###############################################################
#  Generated by:      Cadence Innovus 21.10-p004_1
#  OS:                Linux x86_64(Host ID UETLHR)
#  Generated on:      Wed Nov 23 18:34:10 2022
#  Design:            SoC_Tile
#  Command:           write_lef_abstract SoC_Tile.lef -top_layer met4 -stripe_pins -pg_pin_layers met4
###############################################################

VERSION 5.8 ;

BUSBITCHARS "[]" ;
DIVIDERCHAR "/" ;

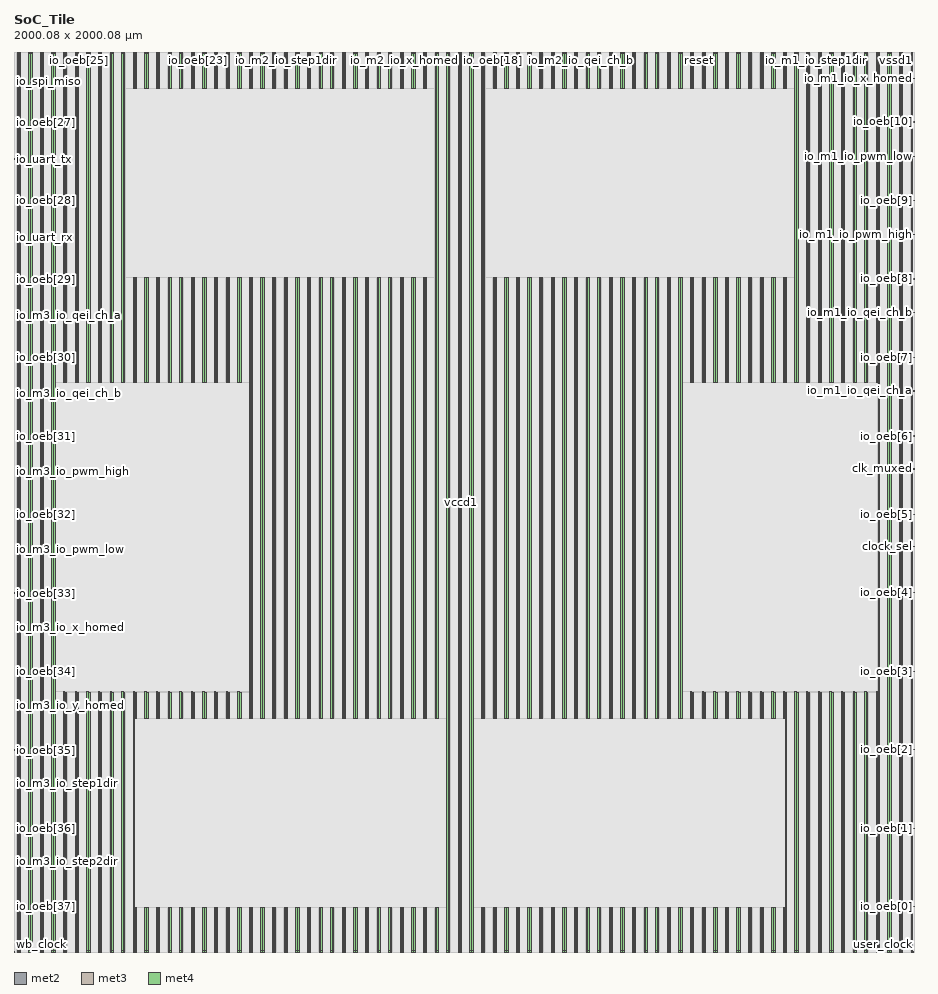
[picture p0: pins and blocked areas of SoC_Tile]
MACRO SoC_Tile
  CLASS BLOCK ;
  SIZE 2000.080000 BY 2000.080000 ;
  FOREIGN SoC_Tile 0.000000 0.000000 ;
  ORIGIN 0 0 ;
  SYMMETRY X Y R90 ;
  PIN user_clock
    DIRECTION INPUT ;
    USE SIGNAL ;
    ANTENNAPARTIALMETALAREA 0.1666 LAYER met2  ;
    ANTENNAPARTIALMETALSIDEAREA 0.672 LAYER met2  ;
    ANTENNAPARTIALCUTAREA 0.04 LAYER via2  ;
    ANTENNAPARTIALMETALAREA 285.163 LAYER met3  ;
    ANTENNAPARTIALMETALSIDEAREA 1521.34 LAYER met3  ;
    ANTENNAPARTIALCUTAREA 0.04 LAYER via3  ;
    ANTENNAPARTIALMETALAREA 0.6516 LAYER met4  ;
    ANTENNAPARTIALMETALSIDEAREA 4.416 LAYER met4  ;
    ANTENNAMODEL OXIDE1 ;
    ANTENNAGATEAREA 0.2475 LAYER met4  ;
    ANTENNAMAXAREACAR 17.5527 LAYER met4  ;
    ANTENNAMAXSIDEAREACAR 98.9939 LAYER met4  ;
    ANTENNAMAXCUTCAR 0.530909 LAYER via4  ;
    PORT
      LAYER met2 ;
        RECT 1999.780000 0.000000 1999.920000 0.485000 ;
    END
  END user_clock
  PIN wb_clock
    DIRECTION INPUT ;
    USE SIGNAL ;
    ANTENNAPARTIALMETALAREA 0.1666 LAYER met2  ;
    ANTENNAPARTIALMETALSIDEAREA 0.672 LAYER met2  ;
    ANTENNAPARTIALCUTAREA 0.04 LAYER via2  ;
    ANTENNAPARTIALMETALAREA 302.344 LAYER met3  ;
    ANTENNAPARTIALMETALSIDEAREA 1612.97 LAYER met3  ;
    ANTENNAPARTIALCUTAREA 0.04 LAYER via3  ;
    ANTENNAPARTIALMETALAREA 0.3258 LAYER met4  ;
    ANTENNAPARTIALMETALSIDEAREA 2.208 LAYER met4  ;
    ANTENNAMODEL OXIDE1 ;
    ANTENNAGATEAREA 0.2475 LAYER met4  ;
    ANTENNAMAXAREACAR 30.9105 LAYER met4  ;
    ANTENNAMAXSIDEAREACAR 167.519 LAYER met4  ;
    ANTENNAMAXCUTCAR 0.530909 LAYER via4  ;
    PORT
      LAYER met2 ;
        RECT 0.160000 0.000000 0.300000 0.485000 ;
    END
  END wb_clock
  PIN clock_sel
    DIRECTION INPUT ;
    USE SIGNAL ;
    ANTENNAPARTIALMETALAREA 20.4744 LAYER met3  ;
    ANTENNAPARTIALMETALSIDEAREA 109.64 LAYER met3  ;
    ANTENNAPARTIALCUTAREA 0.04 LAYER via3  ;
    ANTENNADIFFAREA 0.4347 LAYER met4  ;
    ANTENNAPARTIALMETALAREA 146.368 LAYER met4  ;
    ANTENNAPARTIALMETALSIDEAREA 782.512 LAYER met4  ;
    ANTENNAMODEL OXIDE1 ;
    ANTENNAGATEAREA 0.7425 LAYER met4  ;
    ANTENNAMAXAREACAR 242.909 LAYER met4  ;
    ANTENNAMAXSIDEAREACAR 1291.42 LAYER met4  ;
    ANTENNAMAXCUTCAR 0.530909 LAYER via4  ;
    PORT
      LAYER met3 ;
        RECT 1999.280000 900.110000 2000.080000 900.410000 ;
    END
  END clock_sel
  PIN clk_muxed
    DIRECTION OUTPUT ;
    USE SIGNAL ;
    ANTENNADIFFAREA 4.5209 LAYER met3  ;
    ANTENNAPARTIALMETALAREA 2.5104 LAYER met3  ;
    ANTENNAPARTIALMETALSIDEAREA 13.384 LAYER met3  ;
    PORT
      LAYER met3 ;
        RECT 1999.280000 1073.350000 2000.080000 1073.650000 ;
    END
  END clk_muxed
  PIN reset
    DIRECTION INPUT ;
    USE SIGNAL ;
    ANTENNAPARTIALMETALAREA 17.8079 LAYER met2  ;
    ANTENNAPARTIALMETALSIDEAREA 88.5045 LAYER met2  ;
    ANTENNAMODEL OXIDE1 ;
    ANTENNAGATEAREA 1.7325 LAYER met2  ;
    ANTENNAMAXAREACAR 10.2787 LAYER met2  ;
    ANTENNAMAXSIDEAREACAR 51.0849 LAYER met2  ;
    ANTENNAPARTIALCUTAREA 0.04 LAYER via2  ;
    ANTENNAMAXCUTCAR 0.023088 LAYER via2  ;
    ANTENNAPARTIALMETALAREA 5.506 LAYER met3  ;
    ANTENNAPARTIALMETALSIDEAREA 29.832 LAYER met3  ;
    ANTENNAGATEAREA 1.7325 LAYER met3  ;
    ANTENNAMAXAREACAR 13.4568 LAYER met3  ;
    ANTENNAMAXSIDEAREACAR 68.3039 LAYER met3  ;
    ANTENNAPARTIALCUTAREA 0.04 LAYER via3  ;
    ANTENNAMAXCUTCAR 0.046176 LAYER via3  ;
    ANTENNAPARTIALMETALAREA 117.788 LAYER met4  ;
    ANTENNAPARTIALMETALSIDEAREA 628.672 LAYER met4  ;
    ANTENNAGATEAREA 1.8915 LAYER met4  ;
    ANTENNAMAXAREACAR 75.729 LAYER met4  ;
    ANTENNAMAXSIDEAREACAR 400.671 LAYER met4  ;
    ANTENNAMAXCUTCAR 0.046176 LAYER via4  ;
    PORT
      LAYER met2 ;
        RECT 1521.380000 1999.595000 1521.520000 2000.080000 ;
    END
  END reset
  PIN io_uart_tx
    DIRECTION OUTPUT ;
    USE SIGNAL ;
    ANTENNADIFFAREA 1.782 LAYER met3  ;
    ANTENNAPARTIALMETALAREA 76.071 LAYER met3  ;
    ANTENNAPARTIALMETALSIDEAREA 406.648 LAYER met3  ;
    PORT
      LAYER met3 ;
        RECT 0.000000 1762.040000 0.800000 1762.340000 ;
    END
  END io_uart_tx
  PIN io_uart_rx
    DIRECTION INPUT ;
    USE SIGNAL ;
    ANTENNAPARTIALMETALAREA 20.7766 LAYER met3  ;
    ANTENNAPARTIALMETALSIDEAREA 110.8 LAYER met3  ;
    ANTENNAPARTIALCUTAREA 0.04 LAYER via3  ;
    ANTENNAPARTIALMETALAREA 0.6516 LAYER met4  ;
    ANTENNAPARTIALMETALSIDEAREA 4.416 LAYER met4  ;
    ANTENNAMODEL OXIDE1 ;
    ANTENNAGATEAREA 0.126 LAYER met4  ;
    ANTENNAMAXAREACAR 23.8119 LAYER met4  ;
    ANTENNAMAXSIDEAREACAR 118.73 LAYER met4  ;
    ANTENNAMAXCUTCAR 1.04286 LAYER via4  ;
    PORT
      LAYER met3 ;
        RECT 0.000000 1588.190000 0.800000 1588.490000 ;
    END
  END io_uart_rx
  PIN io_spi_cs
    DIRECTION OUTPUT ;
    USE SIGNAL ;
    ANTENNAPARTIALMETALAREA 74.8488 LAYER met2  ;
    ANTENNAPARTIALMETALSIDEAREA 373.772 LAYER met2  ;
    ANTENNAPARTIALCUTAREA 0.04 LAYER via2  ;
    ANTENNADIFFAREA 1.782 LAYER met3  ;
    ANTENNAPARTIALMETALAREA 45.0138 LAYER met3  ;
    ANTENNAPARTIALMETALSIDEAREA 240.544 LAYER met3  ;
    PORT
      LAYER met2 ;
        RECT 341.940000 1999.595000 342.080000 2000.080000 ;
    END
  END io_spi_cs
  PIN io_spi_clk
    DIRECTION OUTPUT ;
    USE SIGNAL ;
    ANTENNADIFFAREA 1.782 LAYER met2  ;
    ANTENNAPARTIALMETALAREA 62.6847 LAYER met2  ;
    ANTENNAPARTIALMETALSIDEAREA 313.198 LAYER met2  ;
    PORT
      LAYER met2 ;
        RECT 212.680000 1999.595000 212.820000 2000.080000 ;
    END
  END io_spi_clk
  PIN io_spi_mosi
    DIRECTION OUTPUT ;
    USE SIGNAL ;
    ANTENNADIFFAREA 1.782 LAYER met2  ;
    ANTENNAPARTIALMETALAREA 0.6635 LAYER met2  ;
    ANTENNAPARTIALMETALSIDEAREA 3.2095 LAYER met2  ;
    PORT
      LAYER met2 ;
        RECT 82.500000 1999.595000 82.640000 2000.080000 ;
    END
  END io_spi_mosi
  PIN io_spi_miso
    DIRECTION INPUT ;
    USE SIGNAL ;
    ANTENNAPARTIALMETALAREA 20.5936 LAYER met3  ;
    ANTENNAPARTIALMETALSIDEAREA 109.824 LAYER met3  ;
    ANTENNAPARTIALCUTAREA 0.04 LAYER via3  ;
    ANTENNAPARTIALMETALAREA 0.6516 LAYER met4  ;
    ANTENNAPARTIALMETALSIDEAREA 4.416 LAYER met4  ;
    ANTENNAMODEL OXIDE1 ;
    ANTENNAGATEAREA 0.1965 LAYER met4  ;
    ANTENNAMAXAREACAR 45.4382 LAYER met4  ;
    ANTENNAMAXSIDEAREACAR 232.361 LAYER met4  ;
    ANTENNAMAXCUTCAR 0.668702 LAYER via4  ;
    PORT
      LAYER met3 ;
        RECT 0.000000 1935.280000 0.800000 1935.580000 ;
    END
  END io_spi_miso
  PIN io_m1_io_qei_ch_a
    DIRECTION INPUT ;
    USE SIGNAL ;
    ANTENNAPARTIALMETALAREA 3.2004 LAYER met3  ;
    ANTENNAPARTIALMETALSIDEAREA 17.064 LAYER met3  ;
    ANTENNAMODEL OXIDE1 ;
    ANTENNAGATEAREA 0.126 LAYER met3  ;
    ANTENNAMAXAREACAR 30.1706 LAYER met3  ;
    ANTENNAMAXSIDEAREACAR 147.591 LAYER met3  ;
    ANTENNAMAXCUTCAR 0.725397 LAYER via3  ;
    PORT
      LAYER met3 ;
        RECT 1999.280000 1246.590000 2000.080000 1246.890000 ;
    END
  END io_m1_io_qei_ch_a
  PIN io_m1_io_qei_ch_b
    DIRECTION INPUT ;
    USE SIGNAL ;
    ANTENNAPARTIALMETALAREA 0.1644 LAYER met3  ;
    ANTENNAPARTIALMETALSIDEAREA 0.872 LAYER met3  ;
    ANTENNAMODEL OXIDE1 ;
    ANTENNAGATEAREA 0.1965 LAYER met3  ;
    ANTENNAMAXAREACAR 3.38422 LAYER met3  ;
    ANTENNAMAXSIDEAREACAR 13.8601 LAYER met3  ;
    ANTENNAMAXCUTCAR 0.46514 LAYER via3  ;
    PORT
      LAYER met3 ;
        RECT 1999.280000 1420.440000 2000.080000 1420.740000 ;
    END
  END io_m1_io_qei_ch_b
  PIN io_m1_io_pwm_high
    DIRECTION OUTPUT ;
    USE SIGNAL ;
    ANTENNADIFFAREA 1.782 LAYER met3  ;
    ANTENNAPARTIALMETALAREA 4.9944 LAYER met3  ;
    ANTENNAPARTIALMETALSIDEAREA 26.632 LAYER met3  ;
    PORT
      LAYER met3 ;
        RECT 1999.280000 1593.680000 2000.080000 1593.980000 ;
    END
  END io_m1_io_pwm_high
  PIN io_m1_io_pwm_low
    DIRECTION OUTPUT ;
    USE SIGNAL ;
    ANTENNADIFFAREA 1.782 LAYER met3  ;
    ANTENNAPARTIALMETALAREA 5.6844 LAYER met3  ;
    ANTENNAPARTIALMETALSIDEAREA 30.312 LAYER met3  ;
    PORT
      LAYER met3 ;
        RECT 1999.280000 1766.920000 2000.080000 1767.220000 ;
    END
  END io_m1_io_pwm_low
  PIN io_m1_io_x_homed
    DIRECTION INPUT ;
    USE SIGNAL ;
    ANTENNAPARTIALMETALAREA 0.5784 LAYER met3  ;
    ANTENNAPARTIALMETALSIDEAREA 3.08 LAYER met3  ;
    ANTENNAMODEL OXIDE1 ;
    ANTENNAGATEAREA 0.213 LAYER met3  ;
    ANTENNAMAXAREACAR 18.454 LAYER met3  ;
    ANTENNAMAXSIDEAREACAR 90.2911 LAYER met3  ;
    ANTENNAMAXCUTCAR 0.429108 LAYER via3  ;
    PORT
      LAYER met3 ;
        RECT 1999.280000 1940.770000 2000.080000 1941.070000 ;
    END
  END io_m1_io_x_homed
  PIN io_m1_io_y_homed
    DIRECTION INPUT ;
    USE SIGNAL ;
    ANTENNAPARTIALMETALAREA 10.2647 LAYER met2  ;
    ANTENNAPARTIALMETALSIDEAREA 51.2155 LAYER met2  ;
    ANTENNAMODEL OXIDE1 ;
    ANTENNAGATEAREA 0.1965 LAYER met2  ;
    ANTENNAMAXAREACAR 53.2824 LAYER met2  ;
    ANTENNAMAXSIDEAREACAR 263.417 LAYER met2  ;
    ANTENNAMAXCUTCAR 0.261578 LAYER via2  ;
    PORT
      LAYER met2 ;
        RECT 1913.760000 1999.595000 1913.900000 2000.080000 ;
    END
  END io_m1_io_y_homed
  PIN io_m1_io_step1dir
    DIRECTION OUTPUT ;
    USE SIGNAL ;
    ANTENNAPARTIALMETALAREA 86.4766 LAYER met2  ;
    ANTENNAPARTIALMETALSIDEAREA 432.222 LAYER met2  ;
    ANTENNAPARTIALCUTAREA 0.04 LAYER via2  ;
    ANTENNAPARTIALMETALAREA 133.57 LAYER met3  ;
    ANTENNAPARTIALMETALSIDEAREA 712.84 LAYER met3  ;
    ANTENNAPARTIALCUTAREA 0.04 LAYER via3  ;
    ANTENNADIFFAREA 1.782 LAYER met4  ;
    ANTENNAPARTIALMETALAREA 24.2748 LAYER met4  ;
    ANTENNAPARTIALMETALSIDEAREA 129.936 LAYER met4  ;
    PORT
      LAYER met2 ;
        RECT 1782.660000 1999.595000 1782.800000 2000.080000 ;
    END
  END io_m1_io_step1dir
  PIN io_m1_io_step2dir
    DIRECTION OUTPUT ;
    USE SIGNAL ;
    ANTENNAPARTIALMETALAREA 11.1538 LAYER met2  ;
    ANTENNAPARTIALMETALSIDEAREA 55.608 LAYER met2  ;
    ANTENNAPARTIALCUTAREA 0.04 LAYER via2  ;
    ANTENNADIFFAREA 1.782 LAYER met3  ;
    ANTENNAPARTIALMETALAREA 156.496 LAYER met3  ;
    ANTENNAPARTIALMETALSIDEAREA 835.584 LAYER met3  ;
    PORT
      LAYER met2 ;
        RECT 1652.020000 1999.595000 1652.160000 2000.080000 ;
    END
  END io_m1_io_step2dir
  PIN io_m2_io_qei_ch_a
    DIRECTION INPUT ;
    USE SIGNAL ;
    ANTENNAPARTIALMETALAREA 0.6159 LAYER met2  ;
    ANTENNAPARTIALMETALSIDEAREA 2.9715 LAYER met2  ;
    ANTENNAMODEL OXIDE1 ;
    ANTENNAGATEAREA 0.126 LAYER met2  ;
    ANTENNAMAXAREACAR 9.67222 LAYER met2  ;
    ANTENNAMAXSIDEAREACAR 36.6349 LAYER met2  ;
    ANTENNAMAXCUTCAR 0.407937 LAYER via2  ;
    PORT
      LAYER met2 ;
        RECT 1390.280000 1999.595000 1390.420000 2000.080000 ;
    END
  END io_m2_io_qei_ch_a
  PIN io_m2_io_qei_ch_b
    DIRECTION INPUT ;
    USE SIGNAL ;
    ANTENNAPARTIALMETALAREA 0.7447 LAYER met2  ;
    ANTENNAPARTIALMETALSIDEAREA 3.6155 LAYER met2  ;
    ANTENNAMODEL OXIDE1 ;
    ANTENNAGATEAREA 0.126 LAYER met2  ;
    ANTENNAMAXAREACAR 8.97063 LAYER met2  ;
    ANTENNAMAXSIDEAREACAR 33.6627 LAYER met2  ;
    ANTENNAMAXCUTCAR 0.407937 LAYER via2  ;
    PORT
      LAYER met2 ;
        RECT 1259.640000 1999.595000 1259.780000 2000.080000 ;
    END
  END io_m2_io_qei_ch_b
  PIN io_m2_io_pwm_high
    DIRECTION OUTPUT ;
    USE SIGNAL ;
    ANTENNAPARTIALMETALAREA 84.414 LAYER met2  ;
    ANTENNAPARTIALMETALSIDEAREA 421.673 LAYER met2  ;
    ANTENNAPARTIALCUTAREA 0.04 LAYER via2  ;
    ANTENNADIFFAREA 1.782 LAYER met3  ;
    ANTENNAPARTIALMETALAREA 66.1638 LAYER met3  ;
    ANTENNAPARTIALMETALSIDEAREA 353.344 LAYER met3  ;
    PORT
      LAYER met2 ;
        RECT 1129.000000 1999.595000 1129.140000 2000.080000 ;
    END
  END io_m2_io_pwm_high
  PIN io_m2_io_pwm_low
    DIRECTION OUTPUT ;
    USE SIGNAL ;
    ANTENNAPARTIALMETALAREA 60.9854 LAYER met2  ;
    ANTENNAPARTIALMETALSIDEAREA 304.766 LAYER met2  ;
    ANTENNAPARTIALCUTAREA 0.04 LAYER via2  ;
    ANTENNAPARTIALMETALAREA 2.401 LAYER met3  ;
    ANTENNAPARTIALMETALSIDEAREA 13.272 LAYER met3  ;
    ANTENNAPARTIALCUTAREA 0.04 LAYER via3  ;
    ANTENNADIFFAREA 1.782 LAYER met4  ;
    ANTENNAPARTIALMETALAREA 29.5818 LAYER met4  ;
    ANTENNAPARTIALMETALSIDEAREA 158.24 LAYER met4  ;
    PORT
      LAYER met2 ;
        RECT 997.900000 1999.595000 998.040000 2000.080000 ;
    END
  END io_m2_io_pwm_low
  PIN io_m2_io_x_homed
    DIRECTION INPUT ;
    USE SIGNAL ;
    ANTENNAPARTIALMETALAREA 6.5043 LAYER met2  ;
    ANTENNAPARTIALMETALSIDEAREA 32.4135 LAYER met2  ;
    ANTENNAMODEL OXIDE1 ;
    ANTENNAGATEAREA 0.126 LAYER met2  ;
    ANTENNAMAXAREACAR 54.6817 LAYER met2  ;
    ANTENNAMAXSIDEAREACAR 262.218 LAYER met2  ;
    ANTENNAMAXCUTCAR 0.407937 LAYER via2  ;
    PORT
      LAYER met2 ;
        RECT 867.260000 1999.595000 867.400000 2000.080000 ;
    END
  END io_m2_io_x_homed
  PIN io_m2_io_y_homed
    DIRECTION INPUT ;
    USE SIGNAL ;
    ANTENNAPARTIALMETALAREA 3.0771 LAYER met2  ;
    ANTENNAPARTIALMETALSIDEAREA 15.2775 LAYER met2  ;
    ANTENNAMODEL OXIDE1 ;
    ANTENNAGATEAREA 0.213 LAYER met2  ;
    ANTENNAMAXAREACAR 16.0087 LAYER met2  ;
    ANTENNAMAXSIDEAREACAR 77.5258 LAYER met2  ;
    ANTENNAMAXCUTCAR 0.241315 LAYER via2  ;
    PORT
      LAYER met2 ;
        RECT 736.160000 1999.595000 736.300000 2000.080000 ;
    END
  END io_m2_io_y_homed
  PIN io_m2_io_step1dir
    DIRECTION OUTPUT ;
    USE SIGNAL ;
    ANTENNAPARTIALMETALAREA 31.1694 LAYER met2  ;
    ANTENNAPARTIALMETALSIDEAREA 155.568 LAYER met2  ;
    ANTENNAPARTIALCUTAREA 0.04 LAYER via2  ;
    ANTENNAPARTIALMETALAREA 0.2509 LAYER met3  ;
    ANTENNAPARTIALMETALSIDEAREA 1.808 LAYER met3  ;
    ANTENNAPARTIALCUTAREA 0.04 LAYER via3  ;
    ANTENNADIFFAREA 1.782 LAYER met4  ;
    ANTENNAPARTIALMETALAREA 104.66 LAYER met4  ;
    ANTENNAPARTIALMETALSIDEAREA 558.656 LAYER met4  ;
    PORT
      LAYER met2 ;
        RECT 605.520000 1999.595000 605.660000 2000.080000 ;
    END
  END io_m2_io_step1dir
  PIN io_m2_io_step2dir
    DIRECTION OUTPUT ;
    USE SIGNAL ;
    ANTENNAPARTIALMETALAREA 81.2458 LAYER met2  ;
    ANTENNAPARTIALMETALSIDEAREA 405.832 LAYER met2  ;
    ANTENNAPARTIALCUTAREA 0.04 LAYER via2  ;
    ANTENNADIFFAREA 1.782 LAYER met3  ;
    ANTENNAPARTIALMETALAREA 68.6088 LAYER met3  ;
    ANTENNAPARTIALMETALSIDEAREA 366.384 LAYER met3  ;
    PORT
      LAYER met2 ;
        RECT 474.880000 1999.595000 475.020000 2000.080000 ;
    END
  END io_m2_io_step2dir
  PIN io_m3_io_qei_ch_a
    DIRECTION INPUT ;
    USE SIGNAL ;
    ANTENNAPARTIALMETALAREA 20.7766 LAYER met3  ;
    ANTENNAPARTIALMETALSIDEAREA 110.8 LAYER met3  ;
    ANTENNAPARTIALCUTAREA 0.04 LAYER via3  ;
    ANTENNAPARTIALMETALAREA 0.6516 LAYER met4  ;
    ANTENNAPARTIALMETALSIDEAREA 4.416 LAYER met4  ;
    ANTENNAMODEL OXIDE1 ;
    ANTENNAGATEAREA 0.1965 LAYER met4  ;
    ANTENNAMAXAREACAR 62.2417 LAYER met4  ;
    ANTENNAMAXSIDEAREACAR 316.379 LAYER met4  ;
    ANTENNAMAXCUTCAR 0.668702 LAYER via4  ;
    PORT
      LAYER met3 ;
        RECT 0.000000 1414.950000 0.800000 1415.250000 ;
    END
  END io_m3_io_qei_ch_a
  PIN io_m3_io_qei_ch_b
    DIRECTION INPUT ;
    USE SIGNAL ;
    ANTENNAPARTIALMETALAREA 0.4404 LAYER met3  ;
    ANTENNAPARTIALMETALSIDEAREA 2.344 LAYER met3  ;
    ANTENNAMODEL OXIDE1 ;
    ANTENNAGATEAREA 0.1965 LAYER met3  ;
    ANTENNAMAXAREACAR 8.75572 LAYER met3  ;
    ANTENNAMAXSIDEAREACAR 40.7583 LAYER met3  ;
    ANTENNAMAXCUTCAR 0.46514 LAYER via3  ;
    PORT
      LAYER met3 ;
        RECT 0.000000 1241.710000 0.800000 1242.010000 ;
    END
  END io_m3_io_qei_ch_b
  PIN io_m3_io_pwm_high
    DIRECTION OUTPUT ;
    USE SIGNAL ;
    ANTENNADIFFAREA 1.782 LAYER met3  ;
    ANTENNAPARTIALMETALAREA 6.6504 LAYER met3  ;
    ANTENNAPARTIALMETALSIDEAREA 35.464 LAYER met3  ;
    PORT
      LAYER met3 ;
        RECT 0.000000 1067.860000 0.800000 1068.160000 ;
    END
  END io_m3_io_pwm_high
  PIN io_m3_io_pwm_low
    DIRECTION OUTPUT ;
    USE SIGNAL ;
    ANTENNADIFFAREA 1.782 LAYER met3  ;
    ANTENNAPARTIALMETALAREA 6.4644 LAYER met3  ;
    ANTENNAPARTIALMETALSIDEAREA 34.472 LAYER met3  ;
    PORT
      LAYER met3 ;
        RECT 0.000000 894.620000 0.800000 894.920000 ;
    END
  END io_m3_io_pwm_low
  PIN io_m3_io_x_homed
    DIRECTION INPUT ;
    USE SIGNAL ;
    ANTENNAPARTIALMETALAREA 4.6704 LAYER met3  ;
    ANTENNAPARTIALMETALSIDEAREA 24.904 LAYER met3  ;
    ANTENNAMODEL OXIDE1 ;
    ANTENNAGATEAREA 0.126 LAYER met3  ;
    ANTENNAMAXAREACAR 60.4262 LAYER met3  ;
    ANTENNAMAXSIDEAREACAR 299.663 LAYER met3  ;
    ANTENNAMAXCUTCAR 0.725397 LAYER via3  ;
    PORT
      LAYER met3 ;
        RECT 0.000000 721.380000 0.800000 721.680000 ;
    END
  END io_m3_io_x_homed
  PIN io_m3_io_y_homed
    DIRECTION INPUT ;
    USE SIGNAL ;
    ANTENNAPARTIALMETALAREA 1.4064 LAYER met3  ;
    ANTENNAPARTIALMETALSIDEAREA 7.496 LAYER met3  ;
    ANTENNAMODEL OXIDE1 ;
    ANTENNAGATEAREA 0.1965 LAYER met3  ;
    ANTENNAMAXAREACAR 13.0509 LAYER met3  ;
    ANTENNAMAXSIDEAREACAR 64.2163 LAYER met3  ;
    ANTENNAMAXCUTCAR 0.46514 LAYER via3  ;
    PORT
      LAYER met3 ;
        RECT 0.000000 547.530000 0.800000 547.830000 ;
    END
  END io_m3_io_y_homed
  PIN io_m3_io_step1dir
    DIRECTION OUTPUT ;
    USE SIGNAL ;
    ANTENNAPARTIALMETALAREA 8.1544 LAYER met3  ;
    ANTENNAPARTIALMETALSIDEAREA 43.952 LAYER met3  ;
    ANTENNAPARTIALCUTAREA 0.04 LAYER via3  ;
    ANTENNADIFFAREA 1.782 LAYER met4  ;
    ANTENNAPARTIALMETALAREA 64.2408 LAYER met4  ;
    ANTENNAPARTIALMETALSIDEAREA 343.088 LAYER met4  ;
    PORT
      LAYER met3 ;
        RECT 0.000000 374.290000 0.800000 374.590000 ;
    END
  END io_m3_io_step1dir
  PIN io_m3_io_step2dir
    DIRECTION OUTPUT ;
    USE SIGNAL ;
    ANTENNAPARTIALMETALAREA 6.9054 LAYER met3  ;
    ANTENNAPARTIALMETALSIDEAREA 37.272 LAYER met3  ;
    ANTENNAPARTIALCUTAREA 0.04 LAYER via3  ;
    ANTENNADIFFAREA 1.782 LAYER met4  ;
    ANTENNAPARTIALMETALAREA 65.0838 LAYER met4  ;
    ANTENNAPARTIALMETALSIDEAREA 347.584 LAYER met4  ;
    PORT
      LAYER met3 ;
        RECT 0.000000 200.440000 0.800000 200.740000 ;
    END
  END io_m3_io_step2dir
  PIN io_oeb[37]
    DIRECTION OUTPUT ;
    USE SIGNAL ;
    ANTENNADIFFAREA 1.782 LAYER met3  ;
    ANTENNAPARTIALMETALAREA 19.929 LAYER met3  ;
    ANTENNAPARTIALMETALSIDEAREA 108.184 LAYER met3  ;
    PORT
      LAYER met3 ;
        RECT 0.000000 100.400000 0.800000 100.700000 ;
    END
  END io_oeb[37]
  PIN io_oeb[36]
    DIRECTION OUTPUT ;
    USE SIGNAL ;
    ANTENNADIFFAREA 1.782 LAYER met3  ;
    ANTENNAPARTIALMETALAREA 19.809 LAYER met3  ;
    ANTENNAPARTIALMETALSIDEAREA 107.064 LAYER met3  ;
    PORT
      LAYER met3 ;
        RECT 0.000000 274.250000 0.800000 274.550000 ;
    END
  END io_oeb[36]
  PIN io_oeb[35]
    DIRECTION OUTPUT ;
    USE SIGNAL ;
    ANTENNAPARTIALMETALAREA 1.5444 LAYER met3  ;
    ANTENNAPARTIALMETALSIDEAREA 8.232 LAYER met3  ;
    PORT
      LAYER met3 ;
        RECT 0.000000 448.710000 0.800000 449.010000 ;
    END
  END io_oeb[35]
  PIN io_oeb[34]
    DIRECTION OUTPUT ;
    USE SIGNAL ;
    ANTENNAPARTIALMETALAREA 1.5444 LAYER met3  ;
    ANTENNAPARTIALMETALSIDEAREA 8.232 LAYER met3  ;
    PORT
      LAYER met3 ;
        RECT 0.000000 623.170000 0.800000 623.470000 ;
    END
  END io_oeb[34]
  PIN io_oeb[33]
    DIRECTION OUTPUT ;
    USE SIGNAL ;
    ANTENNADIFFAREA 1.782 LAYER met3  ;
    ANTENNAPARTIALMETALAREA 19.929 LAYER met3  ;
    ANTENNAPARTIALMETALSIDEAREA 108.184 LAYER met3  ;
    PORT
      LAYER met3 ;
        RECT 0.000000 797.630000 0.800000 797.930000 ;
    END
  END io_oeb[33]
  PIN io_oeb[32]
    DIRECTION OUTPUT ;
    USE SIGNAL ;
    ANTENNADIFFAREA 1.782 LAYER met3  ;
    ANTENNAPARTIALMETALAREA 1.4163 LAYER met3  ;
    ANTENNAPARTIALMETALSIDEAREA 7.544 LAYER met3  ;
    ANTENNAMODEL OXIDE1 ;
    ANTENNAGATEAREA 0.7425 LAYER met3  ;
    ANTENNAMAXAREACAR 2.56215 LAYER met3  ;
    ANTENNAMAXSIDEAREACAR 11.9576 LAYER met3  ;
    ANTENNAMAXCUTCAR 0.123098 LAYER via3  ;
    PORT
      LAYER met3 ;
        RECT 0.000000 972.090000 0.800000 972.390000 ;
    END
  END io_oeb[32]
  PIN io_oeb[31]
    DIRECTION OUTPUT ;
    USE SIGNAL ;
    ANTENNAPARTIALMETALAREA 1.5444 LAYER met3  ;
    ANTENNAPARTIALMETALSIDEAREA 8.232 LAYER met3  ;
    PORT
      LAYER met3 ;
        RECT 0.000000 1145.940000 0.800000 1146.240000 ;
    END
  END io_oeb[31]
  PIN io_oeb[30]
    DIRECTION OUTPUT ;
    USE SIGNAL ;
    ANTENNAPARTIALMETALAREA 1.5444 LAYER met3  ;
    ANTENNAPARTIALMETALSIDEAREA 8.232 LAYER met3  ;
    PORT
      LAYER met3 ;
        RECT 0.000000 1320.400000 0.800000 1320.700000 ;
    END
  END io_oeb[30]
  PIN io_oeb[29]
    DIRECTION OUTPUT ;
    USE SIGNAL ;
    ANTENNADIFFAREA 1.782 LAYER met3  ;
    ANTENNAPARTIALMETALAREA 1.4163 LAYER met3  ;
    ANTENNAPARTIALMETALSIDEAREA 7.544 LAYER met3  ;
    ANTENNAMODEL OXIDE1 ;
    ANTENNAGATEAREA 0.7425 LAYER met3  ;
    ANTENNAMAXAREACAR 2.51663 LAYER met3  ;
    ANTENNAMAXSIDEAREACAR 11.835 LAYER met3  ;
    ANTENNAMAXCUTCAR 0.123098 LAYER via3  ;
    PORT
      LAYER met3 ;
        RECT 0.000000 1494.860000 0.800000 1495.160000 ;
    END
  END io_oeb[29]
  PIN io_oeb[28]
    DIRECTION OUTPUT ;
    USE SIGNAL ;
    ANTENNAPARTIALMETALAREA 1.5444 LAYER met3  ;
    ANTENNAPARTIALMETALSIDEAREA 8.232 LAYER met3  ;
    PORT
      LAYER met3 ;
        RECT 0.000000 1669.320000 0.800000 1669.620000 ;
    END
  END io_oeb[28]
  PIN io_oeb[27]
    DIRECTION OUTPUT ;
    USE SIGNAL ;
    ANTENNAPARTIALMETALAREA 1.5444 LAYER met3  ;
    ANTENNAPARTIALMETALSIDEAREA 8.232 LAYER met3  ;
    PORT
      LAYER met3 ;
        RECT 0.000000 1843.780000 0.800000 1844.080000 ;
    END
  END io_oeb[27]
  PIN io_oeb[26]
    DIRECTION OUTPUT ;
    USE SIGNAL ;
    ANTENNADIFFAREA 2.673 LAYER met2  ;
    ANTENNAPARTIALMETALAREA 21.0473 LAYER met2  ;
    ANTENNAPARTIALMETALSIDEAREA 105.011 LAYER met2  ;
    ANTENNAMODEL OXIDE1 ;
    ANTENNAGATEAREA 0.7425 LAYER met2  ;
    ANTENNAMAXAREACAR 28.3465 LAYER met2  ;
    ANTENNAMAXSIDEAREACAR 141.428 LAYER met2  ;
    PORT
      LAYER met2 ;
        RECT 13.500000 1999.595000 13.640000 2000.080000 ;
    END
  END io_oeb[26]
  PIN io_oeb[25]
    DIRECTION OUTPUT ;
    USE SIGNAL ;
    ANTENNADIFFAREA 2.673 LAYER met2  ;
    ANTENNAPARTIALMETALAREA 21.0634 LAYER met2  ;
    ANTENNAPARTIALMETALSIDEAREA 105.189 LAYER met2  ;
    ANTENNAMODEL OXIDE1 ;
    ANTENNAGATEAREA 0.7425 LAYER met2  ;
    ANTENNAMAXAREACAR 29.3293 LAYER met2  ;
    ANTENNAMAXSIDEAREACAR 145.238 LAYER met2  ;
    ANTENNAMAXCUTCAR 0.0692256 LAYER via2  ;
    PORT
      LAYER met2 ;
        RECT 145.060000 1999.595000 145.200000 2000.080000 ;
    END
  END io_oeb[25]
  PIN io_oeb[24]
    DIRECTION OUTPUT ;
    USE SIGNAL ;
    ANTENNADIFFAREA 2.673 LAYER met2  ;
    ANTENNAPARTIALMETALAREA 0.4905 LAYER met2  ;
    ANTENNAPARTIALMETALSIDEAREA 2.3345 LAYER met2  ;
    ANTENNAMODEL OXIDE1 ;
    ANTENNAGATEAREA 0.99 LAYER met2  ;
    ANTENNAMAXAREACAR 0.495455 LAYER met2  ;
    ANTENNAMAXSIDEAREACAR 2.35808 LAYER met2  ;
    PORT
      LAYER met2 ;
        RECT 276.620000 1999.595000 276.760000 2000.080000 ;
    END
  END io_oeb[24]
  PIN io_oeb[23]
    DIRECTION OUTPUT ;
    USE SIGNAL ;
    ANTENNADIFFAREA 2.673 LAYER met2  ;
    ANTENNAPARTIALMETALAREA 0.5066 LAYER met2  ;
    ANTENNAPARTIALMETALSIDEAREA 2.513 LAYER met2  ;
    ANTENNAMODEL OXIDE1 ;
    ANTENNAGATEAREA 0.99 LAYER met2  ;
    ANTENNAMAXAREACAR 39.1291 LAYER met2  ;
    ANTENNAMAXSIDEAREACAR 194.178 LAYER met2  ;
    ANTENNAMAXCUTCAR 0.0746465 LAYER via2  ;
    PORT
      LAYER met2 ;
        RECT 408.180000 1999.595000 408.320000 2000.080000 ;
    END
  END io_oeb[23]
  PIN io_oeb[22]
    DIRECTION OUTPUT ;
    USE SIGNAL ;
    ANTENNADIFFAREA 1.782 LAYER met2  ;
    ANTENNAPARTIALMETALAREA 0.2351 LAYER met2  ;
    ANTENNAPARTIALMETALSIDEAREA 1.0675 LAYER met2  ;
    ANTENNAMODEL OXIDE1 ;
    ANTENNAGATEAREA 0.99 LAYER met2  ;
    ANTENNAMAXAREACAR 56.7146 LAYER met2  ;
    ANTENNAMAXSIDEAREACAR 282.194 LAYER met2  ;
    ANTENNAMAXCUTCAR 0.0519192 LAYER via2  ;
    PORT
      LAYER met2 ;
        RECT 539.740000 1999.595000 539.880000 2000.080000 ;
    END
  END io_oeb[22]
  PIN io_oeb[21]
    DIRECTION OUTPUT ;
    USE SIGNAL ;
    ANTENNAPARTIALMETALAREA 0.1399 LAYER met2  ;
    ANTENNAPARTIALMETALSIDEAREA 0.5915 LAYER met2  ;
    PORT
      LAYER met2 ;
        RECT 670.840000 1999.595000 670.980000 2000.080000 ;
    END
  END io_oeb[21]
  PIN io_oeb[20]
    DIRECTION OUTPUT ;
    USE SIGNAL ;
    ANTENNAPARTIALMETALAREA 0.1399 LAYER met2  ;
    ANTENNAPARTIALMETALSIDEAREA 0.5915 LAYER met2  ;
    PORT
      LAYER met2 ;
        RECT 802.400000 1999.595000 802.540000 2000.080000 ;
    END
  END io_oeb[20]
  PIN io_oeb[19]
    DIRECTION OUTPUT ;
    USE SIGNAL ;
    ANTENNADIFFAREA 2.673 LAYER met2  ;
    ANTENNAPARTIALMETALAREA 13.1712 LAYER met2  ;
    ANTENNAPARTIALMETALSIDEAREA 65.492 LAYER met2  ;
    ANTENNAMODEL OXIDE1 ;
    ANTENNAGATEAREA 0.7425 LAYER met2  ;
    ANTENNAMAXAREACAR 18.1473 LAYER met2  ;
    ANTENNAMAXSIDEAREACAR 89.1017 LAYER met2  ;
    ANTENNAMAXCUTCAR 0.0692256 LAYER via2  ;
    PORT
      LAYER met2 ;
        RECT 933.960000 1999.595000 934.100000 2000.080000 ;
    END
  END io_oeb[19]
  PIN io_oeb[18]
    DIRECTION OUTPUT ;
    USE SIGNAL ;
    ANTENNADIFFAREA 2.673 LAYER met2  ;
    ANTENNAPARTIALMETALAREA 13.1712 LAYER met2  ;
    ANTENNAPARTIALMETALSIDEAREA 65.492 LAYER met2  ;
    ANTENNAMODEL OXIDE1 ;
    ANTENNAGATEAREA 0.7425 LAYER met2  ;
    ANTENNAMAXAREACAR 17.739 LAYER met2  ;
    ANTENNAMAXSIDEAREACAR 88.2047 LAYER met2  ;
    PORT
      LAYER met2 ;
        RECT 1064.140000 1999.595000 1064.280000 2000.080000 ;
    END
  END io_oeb[18]
  PIN io_oeb[17]
    DIRECTION OUTPUT ;
    USE SIGNAL ;
    ANTENNAPARTIALMETALAREA 0.2043 LAYER met2  ;
    ANTENNAPARTIALMETALSIDEAREA 0.9135 LAYER met2  ;
    PORT
      LAYER met2 ;
        RECT 1197.080000 1999.595000 1197.220000 2000.080000 ;
    END
  END io_oeb[17]
  PIN io_oeb[16]
    DIRECTION OUTPUT ;
    USE SIGNAL ;
    ANTENNAPARTIALMETALAREA 0.1399 LAYER met2  ;
    ANTENNAPARTIALMETALSIDEAREA 0.5915 LAYER met2  ;
    PORT
      LAYER met2 ;
        RECT 1328.640000 1999.595000 1328.780000 2000.080000 ;
    END
  END io_oeb[16]
  PIN io_oeb[15]
    DIRECTION OUTPUT ;
    USE SIGNAL ;
    ANTENNAPARTIALMETALAREA 0.2106 LAYER met2  ;
    ANTENNAPARTIALMETALSIDEAREA 0.945 LAYER met2  ;
    PORT
      LAYER met2 ;
        RECT 1459.740000 1999.595000 1459.880000 2000.080000 ;
    END
  END io_oeb[15]
  PIN io_oeb[14]
    DIRECTION OUTPUT ;
    USE SIGNAL ;
    ANTENNAPARTIALMETALAREA 17.8079 LAYER met2  ;
    ANTENNAPARTIALMETALSIDEAREA 88.5045 LAYER met2  ;
    ANTENNAMODEL OXIDE1 ;
    ANTENNAGATEAREA 1.7325 LAYER met2  ;
    ANTENNAMAXAREACAR 10.2787 LAYER met2  ;
    ANTENNAMAXSIDEAREACAR 51.0849 LAYER met2  ;
    ANTENNAPARTIALCUTAREA 0.04 LAYER via2  ;
    ANTENNAMAXCUTCAR 0.023088 LAYER via2  ;
    ANTENNAPARTIALMETALAREA 5.506 LAYER met3  ;
    ANTENNAPARTIALMETALSIDEAREA 29.832 LAYER met3  ;
    ANTENNAGATEAREA 1.7325 LAYER met3  ;
    ANTENNAMAXAREACAR 13.4568 LAYER met3  ;
    ANTENNAMAXSIDEAREACAR 68.3039 LAYER met3  ;
    ANTENNAPARTIALCUTAREA 0.04 LAYER via3  ;
    ANTENNAMAXCUTCAR 0.046176 LAYER via3  ;
    ANTENNAPARTIALMETALAREA 117.788 LAYER met4  ;
    ANTENNAPARTIALMETALSIDEAREA 628.672 LAYER met4  ;
    ANTENNAGATEAREA 1.8915 LAYER met4  ;
    ANTENNAMAXAREACAR 75.729 LAYER met4  ;
    ANTENNAMAXSIDEAREACAR 400.671 LAYER met4  ;
    ANTENNAMAXCUTCAR 0.046176 LAYER via4  ;
    PORT
      LAYER met2 ;
        RECT 1591.300000 1999.595000 1591.440000 2000.080000 ;
    END
  END io_oeb[14]
  PIN io_oeb[13]
    DIRECTION OUTPUT ;
    USE SIGNAL ;
    ANTENNAPARTIALMETALAREA 17.8079 LAYER met2  ;
    ANTENNAPARTIALMETALSIDEAREA 88.5045 LAYER met2  ;
    ANTENNAMODEL OXIDE1 ;
    ANTENNAGATEAREA 1.7325 LAYER met2  ;
    ANTENNAMAXAREACAR 13.1997 LAYER met2  ;
    ANTENNAMAXSIDEAREACAR 64.3084 LAYER met2  ;
    ANTENNAPARTIALCUTAREA 0.04 LAYER via2  ;
    ANTENNAMAXCUTCAR 0.122617 LAYER via2  ;
    ANTENNAPARTIALMETALAREA 5.506 LAYER met3  ;
    ANTENNAPARTIALMETALSIDEAREA 29.832 LAYER met3  ;
    ANTENNAGATEAREA 1.7325 LAYER met3  ;
    ANTENNAMAXAREACAR 16.3777 LAYER met3  ;
    ANTENNAMAXSIDEAREACAR 81.5275 LAYER met3  ;
    ANTENNAPARTIALCUTAREA 0.04 LAYER via3  ;
    ANTENNAMAXCUTCAR 0.145705 LAYER via3  ;
    ANTENNAPARTIALMETALAREA 117.788 LAYER met4  ;
    ANTENNAPARTIALMETALSIDEAREA 628.672 LAYER met4  ;
    ANTENNAGATEAREA 1.8915 LAYER met4  ;
    ANTENNAMAXAREACAR 78.6499 LAYER met4  ;
    ANTENNAMAXSIDEAREACAR 413.894 LAYER met4  ;
    ANTENNAMAXCUTCAR 0.826415 LAYER via4  ;
    PORT
      LAYER met2 ;
        RECT 1722.860000 1999.595000 1723.000000 2000.080000 ;
    END
  END io_oeb[13]
  PIN io_oeb[12]
    DIRECTION OUTPUT ;
    USE SIGNAL ;
    ANTENNAPARTIALMETALAREA 0.1399 LAYER met2  ;
    ANTENNAPARTIALMETALSIDEAREA 0.5915 LAYER met2  ;
    PORT
      LAYER met2 ;
        RECT 1854.420000 1999.595000 1854.560000 2000.080000 ;
    END
  END io_oeb[12]
  PIN io_oeb[11]
    DIRECTION OUTPUT ;
    USE SIGNAL ;
    ANTENNAPARTIALMETALAREA 0.1399 LAYER met2  ;
    ANTENNAPARTIALMETALSIDEAREA 0.5915 LAYER met2  ;
    PORT
      LAYER met2 ;
        RECT 1985.980000 1999.595000 1986.120000 2000.080000 ;
    END
  END io_oeb[11]
  PIN io_oeb[10]
    DIRECTION OUTPUT ;
    USE SIGNAL ;
    ANTENNADIFFAREA 1.782 LAYER met3  ;
    ANTENNAPARTIALMETALAREA 11.8572 LAYER met3  ;
    ANTENNAPARTIALMETALSIDEAREA 64.664 LAYER met3  ;
    PORT
      LAYER met3 ;
        RECT 1999.280000 1844.390000 2000.080000 1844.690000 ;
    END
  END io_oeb[10]
  PIN io_oeb[9]
    DIRECTION OUTPUT ;
    USE SIGNAL ;
    ANTENNADIFFAREA 1.782 LAYER met3  ;
    ANTENNAPARTIALMETALAREA 11.7372 LAYER met3  ;
    ANTENNAPARTIALMETALSIDEAREA 63.544 LAYER met3  ;
    PORT
      LAYER met3 ;
        RECT 1999.280000 1669.930000 2000.080000 1670.230000 ;
    END
  END io_oeb[9]
  PIN io_oeb[8]
    DIRECTION OUTPUT ;
    USE SIGNAL ;
    ANTENNAPARTIALMETALAREA 0.8544 LAYER met3  ;
    ANTENNAPARTIALMETALSIDEAREA 4.552 LAYER met3  ;
    PORT
      LAYER met3 ;
        RECT 1999.280000 1495.470000 2000.080000 1495.770000 ;
    END
  END io_oeb[8]
  PIN io_oeb[7]
    DIRECTION OUTPUT ;
    USE SIGNAL ;
    ANTENNAPARTIALMETALAREA 1.1304 LAYER met3  ;
    ANTENNAPARTIALMETALSIDEAREA 6.024 LAYER met3  ;
    PORT
      LAYER met3 ;
        RECT 1999.280000 1321.010000 2000.080000 1321.310000 ;
    END
  END io_oeb[7]
  PIN io_oeb[6]
    DIRECTION OUTPUT ;
    USE SIGNAL ;
    ANTENNADIFFAREA 1.782 LAYER met3  ;
    ANTENNAPARTIALMETALAREA 11.8572 LAYER met3  ;
    ANTENNAPARTIALMETALSIDEAREA 64.664 LAYER met3  ;
    PORT
      LAYER met3 ;
        RECT 1999.280000 1146.550000 2000.080000 1146.850000 ;
    END
  END io_oeb[6]
  PIN io_oeb[5]
    DIRECTION OUTPUT ;
    USE SIGNAL ;
    ANTENNAPARTIALMETALAREA 1.1304 LAYER met3  ;
    ANTENNAPARTIALMETALSIDEAREA 6.024 LAYER met3  ;
    PORT
      LAYER met3 ;
        RECT 1999.280000 972.700000 2000.080000 973.000000 ;
    END
  END io_oeb[5]
  PIN io_oeb[4]
    DIRECTION OUTPUT ;
    USE SIGNAL ;
    ANTENNAPARTIALMETALAREA 0.8544 LAYER met3  ;
    ANTENNAPARTIALMETALSIDEAREA 4.552 LAYER met3  ;
    PORT
      LAYER met3 ;
        RECT 1999.280000 798.240000 2000.080000 798.540000 ;
    END
  END io_oeb[4]
  PIN io_oeb[3]
    DIRECTION OUTPUT ;
    USE SIGNAL ;
    ANTENNAPARTIALMETALAREA 0.5784 LAYER met3  ;
    ANTENNAPARTIALMETALSIDEAREA 3.08 LAYER met3  ;
    PORT
      LAYER met3 ;
        RECT 1999.280000 623.780000 2000.080000 624.080000 ;
    END
  END io_oeb[3]
  PIN io_oeb[2]
    DIRECTION OUTPUT ;
    USE SIGNAL ;
    ANTENNAPARTIALMETALAREA 0.1644 LAYER met3  ;
    ANTENNAPARTIALMETALSIDEAREA 0.872 LAYER met3  ;
    PORT
      LAYER met3 ;
        RECT 1999.280000 449.320000 2000.080000 449.620000 ;
    END
  END io_oeb[2]
  PIN io_oeb[1]
    DIRECTION OUTPUT ;
    USE SIGNAL ;
    ANTENNAPARTIALMETALAREA 0.4404 LAYER met3  ;
    ANTENNAPARTIALMETALSIDEAREA 2.344 LAYER met3  ;
    PORT
      LAYER met3 ;
        RECT 1999.280000 274.860000 2000.080000 275.160000 ;
    END
  END io_oeb[1]
  PIN io_oeb[0]
    DIRECTION OUTPUT ;
    USE SIGNAL ;
    ANTENNAPARTIALMETALAREA 0.4404 LAYER met3  ;
    ANTENNAPARTIALMETALSIDEAREA 2.344 LAYER met3  ;
    PORT
      LAYER met3 ;
        RECT 1999.280000 101.010000 2000.080000 101.310000 ;
    END
  END io_oeb[0]
  PIN vssd1
    DIRECTION INOUT ;
    USE GROUND ;
    PORT
      LAYER met4 ;
        RECT 1142.210000 1996.980000 1145.310000 2000.080000 ;
    END
    PORT
      LAYER met4 ;
        RECT 1142.210000 0.000000 1145.310000 3.100000 ;
    END
    PORT
      LAYER met4 ;
        RECT 1116.410000 1996.980000 1119.510000 2000.080000 ;
    END
    PORT
      LAYER met4 ;
        RECT 1116.410000 0.000000 1119.510000 3.100000 ;
    END
    PORT
      LAYER met4 ;
        RECT 1090.610000 1996.980000 1093.710000 2000.080000 ;
    END
    PORT
      LAYER met4 ;
        RECT 1090.610000 0.000000 1093.710000 3.100000 ;
    END
    PORT
      LAYER met4 ;
        RECT 1064.810000 1996.980000 1067.910000 2000.080000 ;
    END
    PORT
      LAYER met4 ;
        RECT 1064.810000 0.000000 1067.910000 3.100000 ;
    END
    PORT
      LAYER met4 ;
        RECT 1039.010000 1996.980000 1042.110000 2000.080000 ;
    END
    PORT
      LAYER met4 ;
        RECT 1039.010000 0.000000 1042.110000 3.100000 ;
    END
    PORT
      LAYER met4 ;
        RECT 1013.210000 1996.980000 1016.310000 2000.080000 ;
    END
    PORT
      LAYER met4 ;
        RECT 1013.210000 0.000000 1016.310000 3.100000 ;
    END
    PORT
      LAYER met4 ;
        RECT 987.410000 1996.980000 990.510000 2000.080000 ;
    END
    PORT
      LAYER met4 ;
        RECT 987.410000 0.000000 990.510000 3.100000 ;
    END
    PORT
      LAYER met4 ;
        RECT 961.610000 1996.980000 964.710000 2000.080000 ;
    END
    PORT
      LAYER met4 ;
        RECT 961.610000 0.000000 964.710000 3.100000 ;
    END
    PORT
      LAYER met4 ;
        RECT 935.810000 1996.980000 938.910000 2000.080000 ;
    END
    PORT
      LAYER met4 ;
        RECT 935.810000 0.000000 938.910000 3.100000 ;
    END
    PORT
      LAYER met4 ;
        RECT 910.010000 1996.980000 913.110000 2000.080000 ;
    END
    PORT
      LAYER met4 ;
        RECT 910.010000 0.000000 913.110000 3.100000 ;
    END
    PORT
      LAYER met4 ;
        RECT 884.210000 1996.980000 887.310000 2000.080000 ;
    END
    PORT
      LAYER met4 ;
        RECT 884.210000 0.000000 887.310000 3.100000 ;
    END
    PORT
      LAYER met4 ;
        RECT 858.410000 1996.980000 861.510000 2000.080000 ;
    END
    PORT
      LAYER met4 ;
        RECT 858.410000 0.000000 861.510000 3.100000 ;
    END
    PORT
      LAYER met4 ;
        RECT 1993.610000 1996.980000 1996.710000 2000.080000 ;
    END
    PORT
      LAYER met4 ;
        RECT 1993.610000 0.000000 1996.710000 3.100000 ;
    END
    PORT
      LAYER met4 ;
        RECT 832.610000 1996.980000 835.710000 2000.080000 ;
    END
    PORT
      LAYER met4 ;
        RECT 832.610000 0.000000 835.710000 3.100000 ;
    END
    PORT
      LAYER met4 ;
        RECT 1967.810000 1996.980000 1970.910000 2000.080000 ;
    END
    PORT
      LAYER met4 ;
        RECT 1967.810000 0.000000 1970.910000 3.100000 ;
    END
    PORT
      LAYER met4 ;
        RECT 806.810000 1996.980000 809.910000 2000.080000 ;
    END
    PORT
      LAYER met4 ;
        RECT 806.810000 0.000000 809.910000 3.100000 ;
    END
    PORT
      LAYER met4 ;
        RECT 1942.010000 1996.980000 1945.110000 2000.080000 ;
    END
    PORT
      LAYER met4 ;
        RECT 1942.010000 0.000000 1945.110000 3.100000 ;
    END
    PORT
      LAYER met4 ;
        RECT 781.010000 1996.980000 784.110000 2000.080000 ;
    END
    PORT
      LAYER met4 ;
        RECT 781.010000 0.000000 784.110000 3.100000 ;
    END
    PORT
      LAYER met4 ;
        RECT 1916.210000 1996.980000 1919.310000 2000.080000 ;
    END
    PORT
      LAYER met4 ;
        RECT 1916.210000 0.000000 1919.310000 3.100000 ;
    END
    PORT
      LAYER met4 ;
        RECT 755.210000 1996.980000 758.310000 2000.080000 ;
    END
    PORT
      LAYER met4 ;
        RECT 755.210000 0.000000 758.310000 3.100000 ;
    END
    PORT
      LAYER met4 ;
        RECT 1890.410000 1996.980000 1893.510000 2000.080000 ;
    END
    PORT
      LAYER met4 ;
        RECT 1890.410000 0.000000 1893.510000 3.100000 ;
    END
    PORT
      LAYER met4 ;
        RECT 729.410000 1996.980000 732.510000 2000.080000 ;
    END
    PORT
      LAYER met4 ;
        RECT 729.410000 0.000000 732.510000 3.100000 ;
    END
    PORT
      LAYER met4 ;
        RECT 1864.610000 1996.980000 1867.710000 2000.080000 ;
    END
    PORT
      LAYER met4 ;
        RECT 1864.610000 0.000000 1867.710000 3.100000 ;
    END
    PORT
      LAYER met4 ;
        RECT 703.610000 1996.980000 706.710000 2000.080000 ;
    END
    PORT
      LAYER met4 ;
        RECT 703.610000 0.000000 706.710000 3.100000 ;
    END
    PORT
      LAYER met4 ;
        RECT 1838.810000 1996.980000 1841.910000 2000.080000 ;
    END
    PORT
      LAYER met4 ;
        RECT 1838.810000 0.000000 1841.910000 3.100000 ;
    END
    PORT
      LAYER met4 ;
        RECT 677.810000 1996.980000 680.910000 2000.080000 ;
    END
    PORT
      LAYER met4 ;
        RECT 677.810000 0.000000 680.910000 3.100000 ;
    END
    PORT
      LAYER met4 ;
        RECT 1813.010000 1996.980000 1816.110000 2000.080000 ;
    END
    PORT
      LAYER met4 ;
        RECT 1813.010000 0.000000 1816.110000 3.100000 ;
    END
    PORT
      LAYER met4 ;
        RECT 652.010000 1996.980000 655.110000 2000.080000 ;
    END
    PORT
      LAYER met4 ;
        RECT 652.010000 0.000000 655.110000 3.100000 ;
    END
    PORT
      LAYER met4 ;
        RECT 1787.210000 1996.980000 1790.310000 2000.080000 ;
    END
    PORT
      LAYER met4 ;
        RECT 1787.210000 0.000000 1790.310000 3.100000 ;
    END
    PORT
      LAYER met4 ;
        RECT 626.210000 1996.980000 629.310000 2000.080000 ;
    END
    PORT
      LAYER met4 ;
        RECT 626.210000 0.000000 629.310000 3.100000 ;
    END
    PORT
      LAYER met4 ;
        RECT 1761.410000 1996.980000 1764.510000 2000.080000 ;
    END
    PORT
      LAYER met4 ;
        RECT 1761.410000 0.000000 1764.510000 3.100000 ;
    END
    PORT
      LAYER met4 ;
        RECT 600.410000 1996.980000 603.510000 2000.080000 ;
    END
    PORT
      LAYER met4 ;
        RECT 600.410000 0.000000 603.510000 3.100000 ;
    END
    PORT
      LAYER met4 ;
        RECT 1735.610000 1996.980000 1738.710000 2000.080000 ;
    END
    PORT
      LAYER met4 ;
        RECT 1735.610000 0.000000 1738.710000 3.100000 ;
    END
    PORT
      LAYER met4 ;
        RECT 574.610000 1996.980000 577.710000 2000.080000 ;
    END
    PORT
      LAYER met4 ;
        RECT 574.610000 0.000000 577.710000 3.100000 ;
    END
    PORT
      LAYER met4 ;
        RECT 1709.810000 1996.980000 1712.910000 2000.080000 ;
    END
    PORT
      LAYER met4 ;
        RECT 1709.810000 0.000000 1712.910000 3.100000 ;
    END
    PORT
      LAYER met4 ;
        RECT 548.810000 1996.980000 551.910000 2000.080000 ;
    END
    PORT
      LAYER met4 ;
        RECT 548.810000 0.000000 551.910000 3.100000 ;
    END
    PORT
      LAYER met4 ;
        RECT 1684.010000 1996.980000 1687.110000 2000.080000 ;
    END
    PORT
      LAYER met4 ;
        RECT 1684.010000 0.000000 1687.110000 3.100000 ;
    END
    PORT
      LAYER met4 ;
        RECT 523.010000 1996.980000 526.110000 2000.080000 ;
    END
    PORT
      LAYER met4 ;
        RECT 523.010000 0.000000 526.110000 3.100000 ;
    END
    PORT
      LAYER met4 ;
        RECT 1658.210000 1996.980000 1661.310000 2000.080000 ;
    END
    PORT
      LAYER met4 ;
        RECT 1658.210000 0.000000 1661.310000 3.100000 ;
    END
    PORT
      LAYER met4 ;
        RECT 497.210000 1996.980000 500.310000 2000.080000 ;
    END
    PORT
      LAYER met4 ;
        RECT 497.210000 0.000000 500.310000 3.100000 ;
    END
    PORT
      LAYER met4 ;
        RECT 1632.410000 1996.980000 1635.510000 2000.080000 ;
    END
    PORT
      LAYER met4 ;
        RECT 1632.410000 0.000000 1635.510000 3.100000 ;
    END
    PORT
      LAYER met4 ;
        RECT 471.410000 1996.980000 474.510000 2000.080000 ;
    END
    PORT
      LAYER met4 ;
        RECT 471.410000 0.000000 474.510000 3.100000 ;
    END
    PORT
      LAYER met4 ;
        RECT 1606.610000 1996.980000 1609.710000 2000.080000 ;
    END
    PORT
      LAYER met4 ;
        RECT 1606.610000 0.000000 1609.710000 3.100000 ;
    END
    PORT
      LAYER met4 ;
        RECT 445.610000 1996.980000 448.710000 2000.080000 ;
    END
    PORT
      LAYER met4 ;
        RECT 445.610000 0.000000 448.710000 3.100000 ;
    END
    PORT
      LAYER met4 ;
        RECT 1580.810000 1996.980000 1583.910000 2000.080000 ;
    END
    PORT
      LAYER met4 ;
        RECT 1580.810000 0.000000 1583.910000 3.100000 ;
    END
    PORT
      LAYER met4 ;
        RECT 419.810000 1996.980000 422.910000 2000.080000 ;
    END
    PORT
      LAYER met4 ;
        RECT 419.810000 0.000000 422.910000 3.100000 ;
    END
    PORT
      LAYER met4 ;
        RECT 1555.010000 1996.980000 1558.110000 2000.080000 ;
    END
    PORT
      LAYER met4 ;
        RECT 1555.010000 0.000000 1558.110000 3.100000 ;
    END
    PORT
      LAYER met4 ;
        RECT 394.010000 1996.980000 397.110000 2000.080000 ;
    END
    PORT
      LAYER met4 ;
        RECT 394.010000 0.000000 397.110000 3.100000 ;
    END
    PORT
      LAYER met4 ;
        RECT 1529.210000 1996.980000 1532.310000 2000.080000 ;
    END
    PORT
      LAYER met4 ;
        RECT 1529.210000 0.000000 1532.310000 3.100000 ;
    END
    PORT
      LAYER met4 ;
        RECT 368.210000 1996.980000 371.310000 2000.080000 ;
    END
    PORT
      LAYER met4 ;
        RECT 368.210000 0.000000 371.310000 3.100000 ;
    END
    PORT
      LAYER met4 ;
        RECT 1503.410000 1996.980000 1506.510000 2000.080000 ;
    END
    PORT
      LAYER met4 ;
        RECT 1503.410000 0.000000 1506.510000 3.100000 ;
    END
    PORT
      LAYER met4 ;
        RECT 342.410000 1996.980000 345.510000 2000.080000 ;
    END
    PORT
      LAYER met4 ;
        RECT 342.410000 0.000000 345.510000 3.100000 ;
    END
    PORT
      LAYER met4 ;
        RECT 1477.610000 1996.980000 1480.710000 2000.080000 ;
    END
    PORT
      LAYER met4 ;
        RECT 1477.610000 0.000000 1480.710000 3.100000 ;
    END
    PORT
      LAYER met4 ;
        RECT 316.610000 1996.980000 319.710000 2000.080000 ;
    END
    PORT
      LAYER met4 ;
        RECT 316.610000 0.000000 319.710000 3.100000 ;
    END
    PORT
      LAYER met4 ;
        RECT 1451.810000 1996.980000 1454.910000 2000.080000 ;
    END
    PORT
      LAYER met4 ;
        RECT 1451.810000 0.000000 1454.910000 3.100000 ;
    END
    PORT
      LAYER met4 ;
        RECT 290.810000 1996.980000 293.910000 2000.080000 ;
    END
    PORT
      LAYER met4 ;
        RECT 290.810000 0.000000 293.910000 3.100000 ;
    END
    PORT
      LAYER met4 ;
        RECT 1426.010000 1996.980000 1429.110000 2000.080000 ;
    END
    PORT
      LAYER met4 ;
        RECT 1426.010000 0.000000 1429.110000 3.100000 ;
    END
    PORT
      LAYER met4 ;
        RECT 265.010000 1996.980000 268.110000 2000.080000 ;
    END
    PORT
      LAYER met4 ;
        RECT 265.010000 0.000000 268.110000 3.100000 ;
    END
    PORT
      LAYER met4 ;
        RECT 1400.210000 1996.980000 1403.310000 2000.080000 ;
    END
    PORT
      LAYER met4 ;
        RECT 1400.210000 0.000000 1403.310000 3.100000 ;
    END
    PORT
      LAYER met4 ;
        RECT 239.210000 1996.980000 242.310000 2000.080000 ;
    END
    PORT
      LAYER met4 ;
        RECT 239.210000 0.000000 242.310000 3.100000 ;
    END
    PORT
      LAYER met4 ;
        RECT 1374.410000 1996.980000 1377.510000 2000.080000 ;
    END
    PORT
      LAYER met4 ;
        RECT 1374.410000 0.000000 1377.510000 3.100000 ;
    END
    PORT
      LAYER met4 ;
        RECT 213.410000 1996.980000 216.510000 2000.080000 ;
    END
    PORT
      LAYER met4 ;
        RECT 213.410000 0.000000 216.510000 3.100000 ;
    END
    PORT
      LAYER met4 ;
        RECT 1348.610000 1996.980000 1351.710000 2000.080000 ;
    END
    PORT
      LAYER met4 ;
        RECT 1348.610000 0.000000 1351.710000 3.100000 ;
    END
    PORT
      LAYER met4 ;
        RECT 187.610000 1996.980000 190.710000 2000.080000 ;
    END
    PORT
      LAYER met4 ;
        RECT 187.610000 0.000000 190.710000 3.100000 ;
    END
    PORT
      LAYER met4 ;
        RECT 1322.810000 1996.980000 1325.910000 2000.080000 ;
    END
    PORT
      LAYER met4 ;
        RECT 1322.810000 0.000000 1325.910000 3.100000 ;
    END
    PORT
      LAYER met4 ;
        RECT 161.810000 1996.980000 164.910000 2000.080000 ;
    END
    PORT
      LAYER met4 ;
        RECT 161.810000 0.000000 164.910000 3.100000 ;
    END
    PORT
      LAYER met4 ;
        RECT 1297.010000 1996.980000 1300.110000 2000.080000 ;
    END
    PORT
      LAYER met4 ;
        RECT 1297.010000 0.000000 1300.110000 3.100000 ;
    END
    PORT
      LAYER met4 ;
        RECT 136.010000 1996.980000 139.110000 2000.080000 ;
    END
    PORT
      LAYER met4 ;
        RECT 136.010000 0.000000 139.110000 3.100000 ;
    END
    PORT
      LAYER met4 ;
        RECT 1271.210000 1996.980000 1274.310000 2000.080000 ;
    END
    PORT
      LAYER met4 ;
        RECT 1271.210000 0.000000 1274.310000 3.100000 ;
    END
    PORT
      LAYER met4 ;
        RECT 110.210000 1996.980000 113.310000 2000.080000 ;
    END
    PORT
      LAYER met4 ;
        RECT 110.210000 0.000000 113.310000 3.100000 ;
    END
    PORT
      LAYER met4 ;
        RECT 1245.410000 1996.980000 1248.510000 2000.080000 ;
    END
    PORT
      LAYER met4 ;
        RECT 1245.410000 0.000000 1248.510000 3.100000 ;
    END
    PORT
      LAYER met4 ;
        RECT 84.410000 1996.980000 87.510000 2000.080000 ;
    END
    PORT
      LAYER met4 ;
        RECT 84.410000 0.000000 87.510000 3.100000 ;
    END
    PORT
      LAYER met4 ;
        RECT 1219.610000 1996.980000 1222.710000 2000.080000 ;
    END
    PORT
      LAYER met4 ;
        RECT 1219.610000 0.000000 1222.710000 3.100000 ;
    END
    PORT
      LAYER met4 ;
        RECT 58.610000 1996.980000 61.710000 2000.080000 ;
    END
    PORT
      LAYER met4 ;
        RECT 58.610000 0.000000 61.710000 3.100000 ;
    END
    PORT
      LAYER met4 ;
        RECT 1193.810000 1996.980000 1196.910000 2000.080000 ;
    END
    PORT
      LAYER met4 ;
        RECT 1193.810000 0.000000 1196.910000 3.100000 ;
    END
    PORT
      LAYER met4 ;
        RECT 32.810000 1996.980000 35.910000 2000.080000 ;
    END
    PORT
      LAYER met4 ;
        RECT 32.810000 0.000000 35.910000 3.100000 ;
    END
    PORT
      LAYER met4 ;
        RECT 1168.010000 1996.980000 1171.110000 2000.080000 ;
    END
    PORT
      LAYER met4 ;
        RECT 1168.010000 0.000000 1171.110000 3.100000 ;
    END
    PORT
      LAYER met4 ;
        RECT 7.010000 1996.980000 10.110000 2000.080000 ;
    END
    PORT
      LAYER met4 ;
        RECT 7.010000 0.000000 10.110000 3.100000 ;
    END

# P/G power stripe data as pin
    PORT
      LAYER met4 ;
        RECT 84.410000 0.000000 87.510000 2000.080000 ;
        RECT 58.610000 0.000000 61.710000 2000.080000 ;
        RECT 32.810000 0.000000 35.910000 2000.080000 ;
        RECT 7.010000 0.000000 10.110000 2000.080000 ;
        RECT 729.410000 519.620000 732.510000 1498.000000 ;
        RECT 703.610000 519.620000 706.710000 1498.000000 ;
        RECT 677.810000 519.620000 680.910000 1498.000000 ;
        RECT 652.010000 519.620000 655.110000 1498.000000 ;
        RECT 626.210000 519.620000 629.310000 1498.000000 ;
        RECT 600.410000 519.620000 603.510000 1498.000000 ;
        RECT 574.610000 519.620000 577.710000 1498.000000 ;
        RECT 548.810000 519.620000 551.910000 1498.000000 ;
        RECT 523.010000 519.620000 526.110000 1498.000000 ;
        RECT 910.010000 519.620000 913.110000 1498.000000 ;
        RECT 884.210000 519.620000 887.310000 1498.000000 ;
        RECT 858.410000 519.620000 861.510000 1498.000000 ;
        RECT 832.610000 519.620000 835.710000 1498.000000 ;
        RECT 806.810000 519.620000 809.910000 1498.000000 ;
        RECT 781.010000 519.620000 784.110000 1498.000000 ;
        RECT 755.210000 519.620000 758.310000 1498.000000 ;
        RECT 935.810000 519.620000 938.910000 2000.080000 ;
        RECT 987.410000 0.000000 990.510000 2000.080000 ;
        RECT 961.610000 0.000000 964.710000 2000.080000 ;
        RECT 1245.410000 519.620000 1248.510000 1498.000000 ;
        RECT 1219.610000 519.620000 1222.710000 1498.000000 ;
        RECT 1193.810000 519.620000 1196.910000 1498.000000 ;
        RECT 1168.010000 519.620000 1171.110000 1498.000000 ;
        RECT 1142.210000 519.620000 1145.310000 1498.000000 ;
        RECT 1116.410000 519.620000 1119.510000 1498.000000 ;
        RECT 1090.610000 519.620000 1093.710000 1498.000000 ;
        RECT 1064.810000 519.620000 1067.910000 1498.000000 ;
        RECT 1039.010000 519.620000 1042.110000 2000.080000 ;
        RECT 1013.210000 0.000000 1016.310000 2000.080000 ;
        RECT 1477.610000 519.620000 1480.710000 1498.000000 ;
        RECT 1451.810000 519.620000 1454.910000 1498.000000 ;
        RECT 1426.010000 519.620000 1429.110000 1498.000000 ;
        RECT 1400.210000 519.620000 1403.310000 1498.000000 ;
        RECT 1374.410000 519.620000 1377.510000 1498.000000 ;
        RECT 1348.610000 519.620000 1351.710000 1498.000000 ;
        RECT 1322.810000 519.620000 1325.910000 1498.000000 ;
        RECT 1297.010000 519.620000 1300.110000 1498.000000 ;
        RECT 1271.210000 519.620000 1274.310000 1498.000000 ;
        RECT 1993.610000 0.000000 1996.710000 2000.080000 ;
        RECT 1967.810000 0.000000 1970.910000 2000.080000 ;
        RECT 1942.010000 0.000000 1945.110000 2000.080000 ;
        RECT 265.010000 0.000000 268.110000 578.000000 ;
        RECT 239.210000 0.000000 242.310000 578.000000 ;
        RECT 213.410000 0.000000 216.510000 578.000000 ;
        RECT 187.610000 0.000000 190.710000 578.000000 ;
        RECT 161.810000 0.000000 164.910000 578.000000 ;
        RECT 136.010000 0.000000 139.110000 578.000000 ;
        RECT 110.210000 0.000000 113.310000 578.000000 ;
        RECT 497.210000 0.000000 500.310000 98.000000 ;
        RECT 368.210000 0.000000 371.310000 98.000000 ;
        RECT 342.410000 0.000000 345.510000 98.000000 ;
        RECT 316.610000 0.000000 319.710000 98.000000 ;
        RECT 290.810000 0.000000 293.910000 98.000000 ;
        RECT 471.410000 0.000000 474.510000 98.000000 ;
        RECT 445.610000 0.000000 448.710000 98.000000 ;
        RECT 419.810000 0.000000 422.910000 98.000000 ;
        RECT 394.010000 0.000000 397.110000 98.000000 ;
        RECT 600.410000 0.000000 603.510000 98.000000 ;
        RECT 574.610000 0.000000 577.710000 98.000000 ;
        RECT 548.810000 0.000000 551.910000 98.000000 ;
        RECT 523.010000 0.000000 526.110000 98.000000 ;
        RECT 729.410000 0.000000 732.510000 98.000000 ;
        RECT 703.610000 0.000000 706.710000 98.000000 ;
        RECT 677.810000 0.000000 680.910000 98.000000 ;
        RECT 652.010000 0.000000 655.110000 98.000000 ;
        RECT 626.210000 0.000000 629.310000 98.000000 ;
        RECT 858.410000 0.000000 861.510000 98.000000 ;
        RECT 832.610000 0.000000 835.710000 98.000000 ;
        RECT 806.810000 0.000000 809.910000 98.000000 ;
        RECT 781.010000 0.000000 784.110000 98.000000 ;
        RECT 755.210000 0.000000 758.310000 98.000000 ;
        RECT 935.810000 0.000000 938.910000 98.000000 ;
        RECT 910.010000 0.000000 913.110000 98.000000 ;
        RECT 884.210000 0.000000 887.310000 98.000000 ;
        RECT 497.210000 519.620000 500.310000 578.000000 ;
        RECT 368.210000 519.620000 371.310000 578.000000 ;
        RECT 342.410000 519.620000 345.510000 578.000000 ;
        RECT 316.610000 519.620000 319.710000 578.000000 ;
        RECT 290.810000 519.620000 293.910000 578.000000 ;
        RECT 471.410000 519.620000 474.510000 578.000000 ;
        RECT 445.610000 519.620000 448.710000 578.000000 ;
        RECT 419.810000 519.620000 422.910000 578.000000 ;
        RECT 394.010000 519.620000 397.110000 578.000000 ;
        RECT 1916.210000 0.000000 1919.310000 578.000000 ;
        RECT 1890.410000 0.000000 1893.510000 578.000000 ;
        RECT 1864.610000 0.000000 1867.710000 578.000000 ;
        RECT 1838.810000 0.000000 1841.910000 578.000000 ;
        RECT 1813.010000 0.000000 1816.110000 578.000000 ;
        RECT 1787.210000 0.000000 1790.310000 578.000000 ;
        RECT 1761.410000 0.000000 1764.510000 578.000000 ;
        RECT 1735.610000 0.000000 1738.710000 578.000000 ;
        RECT 1116.410000 0.000000 1119.510000 98.000000 ;
        RECT 1090.610000 0.000000 1093.710000 98.000000 ;
        RECT 1064.810000 0.000000 1067.910000 98.000000 ;
        RECT 1039.010000 0.000000 1042.110000 98.000000 ;
        RECT 1245.410000 0.000000 1248.510000 98.000000 ;
        RECT 1219.610000 0.000000 1222.710000 98.000000 ;
        RECT 1193.810000 0.000000 1196.910000 98.000000 ;
        RECT 1168.010000 0.000000 1171.110000 98.000000 ;
        RECT 1142.210000 0.000000 1145.310000 98.000000 ;
        RECT 1374.410000 0.000000 1377.510000 98.000000 ;
        RECT 1348.610000 0.000000 1351.710000 98.000000 ;
        RECT 1322.810000 0.000000 1325.910000 98.000000 ;
        RECT 1297.010000 0.000000 1300.110000 98.000000 ;
        RECT 1271.210000 0.000000 1274.310000 98.000000 ;
        RECT 1477.610000 0.000000 1480.710000 98.000000 ;
        RECT 1451.810000 0.000000 1454.910000 98.000000 ;
        RECT 1426.010000 0.000000 1429.110000 98.000000 ;
        RECT 1400.210000 0.000000 1403.310000 98.000000 ;
        RECT 1606.610000 0.000000 1609.710000 98.000000 ;
        RECT 1580.810000 0.000000 1583.910000 98.000000 ;
        RECT 1555.010000 0.000000 1558.110000 98.000000 ;
        RECT 1529.210000 0.000000 1532.310000 98.000000 ;
        RECT 1503.410000 0.000000 1506.510000 98.000000 ;
        RECT 1709.810000 0.000000 1712.910000 98.000000 ;
        RECT 1684.010000 0.000000 1687.110000 98.000000 ;
        RECT 1658.210000 0.000000 1661.310000 98.000000 ;
        RECT 1632.410000 0.000000 1635.510000 98.000000 ;
        RECT 1606.610000 519.620000 1609.710000 578.000000 ;
        RECT 1580.810000 519.620000 1583.910000 578.000000 ;
        RECT 1555.010000 519.620000 1558.110000 578.000000 ;
        RECT 1529.210000 519.620000 1532.310000 578.000000 ;
        RECT 1503.410000 519.620000 1506.510000 578.000000 ;
        RECT 1709.810000 519.620000 1712.910000 578.000000 ;
        RECT 1684.010000 519.620000 1687.110000 578.000000 ;
        RECT 1658.210000 519.620000 1661.310000 578.000000 ;
        RECT 1632.410000 519.620000 1635.510000 578.000000 ;
        RECT 239.210000 1265.100000 242.310000 2000.080000 ;
        RECT 213.410000 1265.100000 216.510000 2000.080000 ;
        RECT 187.610000 1265.100000 190.710000 2000.080000 ;
        RECT 161.810000 1265.100000 164.910000 2000.080000 ;
        RECT 136.010000 1265.100000 139.110000 2000.080000 ;
        RECT 110.210000 1265.100000 113.310000 2000.080000 ;
        RECT 497.210000 1265.100000 500.310000 1498.000000 ;
        RECT 471.410000 1265.100000 474.510000 1498.000000 ;
        RECT 445.610000 1265.100000 448.710000 1498.000000 ;
        RECT 419.810000 1265.100000 422.910000 1498.000000 ;
        RECT 394.010000 1265.100000 397.110000 1498.000000 ;
        RECT 368.210000 1265.100000 371.310000 1498.000000 ;
        RECT 342.410000 1265.100000 345.510000 1498.000000 ;
        RECT 316.610000 1265.100000 319.710000 1498.000000 ;
        RECT 290.810000 1265.100000 293.910000 1498.000000 ;
        RECT 265.010000 1265.100000 268.110000 1498.000000 ;
        RECT 497.210000 1918.540000 500.310000 2000.080000 ;
        RECT 368.210000 1918.540000 371.310000 2000.080000 ;
        RECT 342.410000 1918.540000 345.510000 2000.080000 ;
        RECT 316.610000 1918.540000 319.710000 2000.080000 ;
        RECT 290.810000 1918.540000 293.910000 2000.080000 ;
        RECT 265.010000 1918.540000 268.110000 2000.080000 ;
        RECT 471.410000 1918.540000 474.510000 2000.080000 ;
        RECT 445.610000 1918.540000 448.710000 2000.080000 ;
        RECT 419.810000 1918.540000 422.910000 2000.080000 ;
        RECT 394.010000 1918.540000 397.110000 2000.080000 ;
        RECT 600.410000 1918.540000 603.510000 2000.080000 ;
        RECT 574.610000 1918.540000 577.710000 2000.080000 ;
        RECT 548.810000 1918.540000 551.910000 2000.080000 ;
        RECT 523.010000 1918.540000 526.110000 2000.080000 ;
        RECT 729.410000 1918.540000 732.510000 2000.080000 ;
        RECT 703.610000 1918.540000 706.710000 2000.080000 ;
        RECT 677.810000 1918.540000 680.910000 2000.080000 ;
        RECT 652.010000 1918.540000 655.110000 2000.080000 ;
        RECT 626.210000 1918.540000 629.310000 2000.080000 ;
        RECT 858.410000 1918.540000 861.510000 2000.080000 ;
        RECT 832.610000 1918.540000 835.710000 2000.080000 ;
        RECT 806.810000 1918.540000 809.910000 2000.080000 ;
        RECT 781.010000 1918.540000 784.110000 2000.080000 ;
        RECT 755.210000 1918.540000 758.310000 2000.080000 ;
        RECT 910.010000 1918.540000 913.110000 2000.080000 ;
        RECT 884.210000 1918.540000 887.310000 2000.080000 ;
        RECT 1916.210000 1265.100000 1919.310000 2000.080000 ;
        RECT 1890.410000 1265.100000 1893.510000 2000.080000 ;
        RECT 1864.610000 1265.100000 1867.710000 2000.080000 ;
        RECT 1838.810000 1265.100000 1841.910000 2000.080000 ;
        RECT 1813.010000 1265.100000 1816.110000 2000.080000 ;
        RECT 1787.210000 1265.100000 1790.310000 2000.080000 ;
        RECT 1761.410000 1265.100000 1764.510000 2000.080000 ;
        RECT 1735.610000 1265.100000 1738.710000 2000.080000 ;
        RECT 1709.810000 1265.100000 1712.910000 1498.000000 ;
        RECT 1684.010000 1265.100000 1687.110000 1498.000000 ;
        RECT 1658.210000 1265.100000 1661.310000 1498.000000 ;
        RECT 1632.410000 1265.100000 1635.510000 1498.000000 ;
        RECT 1606.610000 1265.100000 1609.710000 1498.000000 ;
        RECT 1580.810000 1265.100000 1583.910000 1498.000000 ;
        RECT 1555.010000 1265.100000 1558.110000 1498.000000 ;
        RECT 1529.210000 1265.100000 1532.310000 1498.000000 ;
        RECT 1503.410000 1265.100000 1506.510000 1498.000000 ;
        RECT 1116.410000 1918.540000 1119.510000 2000.080000 ;
        RECT 1090.610000 1918.540000 1093.710000 2000.080000 ;
        RECT 1064.810000 1918.540000 1067.910000 2000.080000 ;
        RECT 1245.410000 1918.540000 1248.510000 2000.080000 ;
        RECT 1219.610000 1918.540000 1222.710000 2000.080000 ;
        RECT 1193.810000 1918.540000 1196.910000 2000.080000 ;
        RECT 1168.010000 1918.540000 1171.110000 2000.080000 ;
        RECT 1142.210000 1918.540000 1145.310000 2000.080000 ;
        RECT 1374.410000 1918.540000 1377.510000 2000.080000 ;
        RECT 1348.610000 1918.540000 1351.710000 2000.080000 ;
        RECT 1322.810000 1918.540000 1325.910000 2000.080000 ;
        RECT 1297.010000 1918.540000 1300.110000 2000.080000 ;
        RECT 1271.210000 1918.540000 1274.310000 2000.080000 ;
        RECT 1477.610000 1918.540000 1480.710000 2000.080000 ;
        RECT 1451.810000 1918.540000 1454.910000 2000.080000 ;
        RECT 1426.010000 1918.540000 1429.110000 2000.080000 ;
        RECT 1400.210000 1918.540000 1403.310000 2000.080000 ;
        RECT 1606.610000 1918.540000 1609.710000 2000.080000 ;
        RECT 1580.810000 1918.540000 1583.910000 2000.080000 ;
        RECT 1555.010000 1918.540000 1558.110000 2000.080000 ;
        RECT 1529.210000 1918.540000 1532.310000 2000.080000 ;
        RECT 1503.410000 1918.540000 1506.510000 2000.080000 ;
        RECT 1709.810000 1918.540000 1712.910000 2000.080000 ;
        RECT 1684.010000 1918.540000 1687.110000 2000.080000 ;
        RECT 1658.210000 1918.540000 1661.310000 2000.080000 ;
        RECT 1632.410000 1918.540000 1635.510000 2000.080000 ;
        RECT 497.210000 1265.050000 500.310000 1265.380000 ;
        RECT 239.210000 1265.050000 242.310000 1265.380000 ;
        RECT 213.410000 1265.050000 216.510000 1265.380000 ;
        RECT 187.610000 1265.050000 190.710000 1265.380000 ;
        RECT 161.810000 1265.050000 164.910000 1265.380000 ;
        RECT 136.010000 1265.050000 139.110000 1265.380000 ;
        RECT 110.210000 1265.050000 113.310000 1265.380000 ;
        RECT 471.410000 1265.050000 474.510000 1265.380000 ;
        RECT 445.610000 1265.050000 448.710000 1265.380000 ;
        RECT 419.810000 1265.050000 422.910000 1265.380000 ;
        RECT 394.010000 1265.050000 397.110000 1265.380000 ;
        RECT 368.210000 1265.050000 371.310000 1265.380000 ;
        RECT 342.410000 1265.050000 345.510000 1265.380000 ;
        RECT 316.610000 1265.050000 319.710000 1265.380000 ;
        RECT 290.810000 1265.050000 293.910000 1265.380000 ;
        RECT 265.010000 1265.050000 268.110000 1265.380000 ;
        RECT 1606.610000 1265.050000 1609.710000 1265.380000 ;
        RECT 1580.810000 1265.050000 1583.910000 1265.380000 ;
        RECT 1555.010000 1265.050000 1558.110000 1265.380000 ;
        RECT 1529.210000 1265.050000 1532.310000 1265.380000 ;
        RECT 1503.410000 1265.050000 1506.510000 1265.380000 ;
        RECT 1735.610000 1265.050000 1738.710000 1265.380000 ;
        RECT 1709.810000 1265.050000 1712.910000 1265.380000 ;
        RECT 1684.010000 1265.050000 1687.110000 1265.380000 ;
        RECT 1658.210000 1265.050000 1661.310000 1265.380000 ;
        RECT 1632.410000 1265.050000 1635.510000 1265.380000 ;
        RECT 1916.210000 1265.050000 1919.310000 1265.380000 ;
        RECT 1890.410000 1265.050000 1893.510000 1265.380000 ;
        RECT 1864.610000 1265.050000 1867.710000 1265.380000 ;
        RECT 1838.810000 1265.050000 1841.910000 1265.380000 ;
        RECT 1813.010000 1265.050000 1816.110000 1265.380000 ;
        RECT 1787.210000 1265.050000 1790.310000 1265.380000 ;
        RECT 1761.410000 1265.050000 1764.510000 1265.380000 ;
    END
# end of P/G power stripe data as pin

  END vssd1
  PIN vccd1
    DIRECTION INOUT ;
    USE POWER ;
    PORT
      LAYER met4 ;
        RECT 1146.410000 1996.980000 1149.510000 2000.080000 ;
    END
    PORT
      LAYER met4 ;
        RECT 1146.410000 0.000000 1149.510000 3.100000 ;
    END
    PORT
      LAYER met4 ;
        RECT 1120.610000 1996.980000 1123.710000 2000.080000 ;
    END
    PORT
      LAYER met4 ;
        RECT 1120.610000 0.000000 1123.710000 3.100000 ;
    END
    PORT
      LAYER met4 ;
        RECT 1094.810000 1996.980000 1097.910000 2000.080000 ;
    END
    PORT
      LAYER met4 ;
        RECT 1094.810000 0.000000 1097.910000 3.100000 ;
    END
    PORT
      LAYER met4 ;
        RECT 1069.010000 1996.980000 1072.110000 2000.080000 ;
    END
    PORT
      LAYER met4 ;
        RECT 1069.010000 0.000000 1072.110000 3.100000 ;
    END
    PORT
      LAYER met4 ;
        RECT 1043.210000 1996.980000 1046.310000 2000.080000 ;
    END
    PORT
      LAYER met4 ;
        RECT 1043.210000 0.000000 1046.310000 3.100000 ;
    END
    PORT
      LAYER met4 ;
        RECT 1017.410000 1996.980000 1020.510000 2000.080000 ;
    END
    PORT
      LAYER met4 ;
        RECT 1017.410000 0.000000 1020.510000 3.100000 ;
    END
    PORT
      LAYER met4 ;
        RECT 991.610000 1996.980000 994.710000 2000.080000 ;
    END
    PORT
      LAYER met4 ;
        RECT 991.610000 0.000000 994.710000 3.100000 ;
    END
    PORT
      LAYER met4 ;
        RECT 965.810000 1996.980000 968.910000 2000.080000 ;
    END
    PORT
      LAYER met4 ;
        RECT 965.810000 0.000000 968.910000 3.100000 ;
    END
    PORT
      LAYER met4 ;
        RECT 940.010000 1996.980000 943.110000 2000.080000 ;
    END
    PORT
      LAYER met4 ;
        RECT 940.010000 0.000000 943.110000 3.100000 ;
    END
    PORT
      LAYER met4 ;
        RECT 914.210000 1996.980000 917.310000 2000.080000 ;
    END
    PORT
      LAYER met4 ;
        RECT 914.210000 0.000000 917.310000 3.100000 ;
    END
    PORT
      LAYER met4 ;
        RECT 888.410000 1996.980000 891.510000 2000.080000 ;
    END
    PORT
      LAYER met4 ;
        RECT 888.410000 0.000000 891.510000 3.100000 ;
    END
    PORT
      LAYER met4 ;
        RECT 862.610000 1996.980000 865.710000 2000.080000 ;
    END
    PORT
      LAYER met4 ;
        RECT 862.610000 0.000000 865.710000 3.100000 ;
    END
    PORT
      LAYER met4 ;
        RECT 836.810000 1996.980000 839.910000 2000.080000 ;
    END
    PORT
      LAYER met4 ;
        RECT 836.810000 0.000000 839.910000 3.100000 ;
    END
    PORT
      LAYER met4 ;
        RECT 1972.010000 1996.980000 1975.110000 2000.080000 ;
    END
    PORT
      LAYER met4 ;
        RECT 1972.010000 0.000000 1975.110000 3.100000 ;
    END
    PORT
      LAYER met4 ;
        RECT 811.010000 1996.980000 814.110000 2000.080000 ;
    END
    PORT
      LAYER met4 ;
        RECT 811.010000 0.000000 814.110000 3.100000 ;
    END
    PORT
      LAYER met4 ;
        RECT 1946.210000 1996.980000 1949.310000 2000.080000 ;
    END
    PORT
      LAYER met4 ;
        RECT 1946.210000 0.000000 1949.310000 3.100000 ;
    END
    PORT
      LAYER met4 ;
        RECT 785.210000 1996.980000 788.310000 2000.080000 ;
    END
    PORT
      LAYER met4 ;
        RECT 785.210000 0.000000 788.310000 3.100000 ;
    END
    PORT
      LAYER met4 ;
        RECT 1920.410000 1996.980000 1923.510000 2000.080000 ;
    END
    PORT
      LAYER met4 ;
        RECT 1920.410000 0.000000 1923.510000 3.100000 ;
    END
    PORT
      LAYER met4 ;
        RECT 759.410000 1996.980000 762.510000 2000.080000 ;
    END
    PORT
      LAYER met4 ;
        RECT 759.410000 0.000000 762.510000 3.100000 ;
    END
    PORT
      LAYER met4 ;
        RECT 1894.610000 1996.980000 1897.710000 2000.080000 ;
    END
    PORT
      LAYER met4 ;
        RECT 1894.610000 0.000000 1897.710000 3.100000 ;
    END
    PORT
      LAYER met4 ;
        RECT 733.610000 1996.980000 736.710000 2000.080000 ;
    END
    PORT
      LAYER met4 ;
        RECT 733.610000 0.000000 736.710000 3.100000 ;
    END
    PORT
      LAYER met4 ;
        RECT 1868.810000 1996.980000 1871.910000 2000.080000 ;
    END
    PORT
      LAYER met4 ;
        RECT 1868.810000 0.000000 1871.910000 3.100000 ;
    END
    PORT
      LAYER met4 ;
        RECT 707.810000 1996.980000 710.910000 2000.080000 ;
    END
    PORT
      LAYER met4 ;
        RECT 707.810000 0.000000 710.910000 3.100000 ;
    END
    PORT
      LAYER met4 ;
        RECT 1843.010000 1996.980000 1846.110000 2000.080000 ;
    END
    PORT
      LAYER met4 ;
        RECT 1843.010000 0.000000 1846.110000 3.100000 ;
    END
    PORT
      LAYER met4 ;
        RECT 682.010000 1996.980000 685.110000 2000.080000 ;
    END
    PORT
      LAYER met4 ;
        RECT 682.010000 0.000000 685.110000 3.100000 ;
    END
    PORT
      LAYER met4 ;
        RECT 1817.210000 1996.980000 1820.310000 2000.080000 ;
    END
    PORT
      LAYER met4 ;
        RECT 1817.210000 0.000000 1820.310000 3.100000 ;
    END
    PORT
      LAYER met4 ;
        RECT 656.210000 1996.980000 659.310000 2000.080000 ;
    END
    PORT
      LAYER met4 ;
        RECT 656.210000 0.000000 659.310000 3.100000 ;
    END
    PORT
      LAYER met4 ;
        RECT 1791.410000 1996.980000 1794.510000 2000.080000 ;
    END
    PORT
      LAYER met4 ;
        RECT 1791.410000 0.000000 1794.510000 3.100000 ;
    END
    PORT
      LAYER met4 ;
        RECT 630.410000 1996.980000 633.510000 2000.080000 ;
    END
    PORT
      LAYER met4 ;
        RECT 630.410000 0.000000 633.510000 3.100000 ;
    END
    PORT
      LAYER met4 ;
        RECT 1765.610000 1996.980000 1768.710000 2000.080000 ;
    END
    PORT
      LAYER met4 ;
        RECT 1765.610000 0.000000 1768.710000 3.100000 ;
    END
    PORT
      LAYER met4 ;
        RECT 604.610000 1996.980000 607.710000 2000.080000 ;
    END
    PORT
      LAYER met4 ;
        RECT 604.610000 0.000000 607.710000 3.100000 ;
    END
    PORT
      LAYER met4 ;
        RECT 1739.810000 1996.980000 1742.910000 2000.080000 ;
    END
    PORT
      LAYER met4 ;
        RECT 1739.810000 0.000000 1742.910000 3.100000 ;
    END
    PORT
      LAYER met4 ;
        RECT 578.810000 1996.980000 581.910000 2000.080000 ;
    END
    PORT
      LAYER met4 ;
        RECT 578.810000 0.000000 581.910000 3.100000 ;
    END
    PORT
      LAYER met4 ;
        RECT 1714.010000 1996.980000 1717.110000 2000.080000 ;
    END
    PORT
      LAYER met4 ;
        RECT 1714.010000 0.000000 1717.110000 3.100000 ;
    END
    PORT
      LAYER met4 ;
        RECT 553.010000 1996.980000 556.110000 2000.080000 ;
    END
    PORT
      LAYER met4 ;
        RECT 553.010000 0.000000 556.110000 3.100000 ;
    END
    PORT
      LAYER met4 ;
        RECT 1688.210000 1996.980000 1691.310000 2000.080000 ;
    END
    PORT
      LAYER met4 ;
        RECT 1688.210000 0.000000 1691.310000 3.100000 ;
    END
    PORT
      LAYER met4 ;
        RECT 527.210000 1996.980000 530.310000 2000.080000 ;
    END
    PORT
      LAYER met4 ;
        RECT 527.210000 0.000000 530.310000 3.100000 ;
    END
    PORT
      LAYER met4 ;
        RECT 1662.410000 1996.980000 1665.510000 2000.080000 ;
    END
    PORT
      LAYER met4 ;
        RECT 1662.410000 0.000000 1665.510000 3.100000 ;
    END
    PORT
      LAYER met4 ;
        RECT 501.410000 1996.980000 504.510000 2000.080000 ;
    END
    PORT
      LAYER met4 ;
        RECT 501.410000 0.000000 504.510000 3.100000 ;
    END
    PORT
      LAYER met4 ;
        RECT 1636.610000 1996.980000 1639.710000 2000.080000 ;
    END
    PORT
      LAYER met4 ;
        RECT 1636.610000 0.000000 1639.710000 3.100000 ;
    END
    PORT
      LAYER met4 ;
        RECT 475.610000 1996.980000 478.710000 2000.080000 ;
    END
    PORT
      LAYER met4 ;
        RECT 475.610000 0.000000 478.710000 3.100000 ;
    END
    PORT
      LAYER met4 ;
        RECT 1610.810000 1996.980000 1613.910000 2000.080000 ;
    END
    PORT
      LAYER met4 ;
        RECT 1610.810000 0.000000 1613.910000 3.100000 ;
    END
    PORT
      LAYER met4 ;
        RECT 449.810000 1996.980000 452.910000 2000.080000 ;
    END
    PORT
      LAYER met4 ;
        RECT 449.810000 0.000000 452.910000 3.100000 ;
    END
    PORT
      LAYER met4 ;
        RECT 1585.010000 1996.980000 1588.110000 2000.080000 ;
    END
    PORT
      LAYER met4 ;
        RECT 1585.010000 0.000000 1588.110000 3.100000 ;
    END
    PORT
      LAYER met4 ;
        RECT 424.010000 1996.980000 427.110000 2000.080000 ;
    END
    PORT
      LAYER met4 ;
        RECT 424.010000 0.000000 427.110000 3.100000 ;
    END
    PORT
      LAYER met4 ;
        RECT 1559.210000 1996.980000 1562.310000 2000.080000 ;
    END
    PORT
      LAYER met4 ;
        RECT 1559.210000 0.000000 1562.310000 3.100000 ;
    END
    PORT
      LAYER met4 ;
        RECT 398.210000 1996.980000 401.310000 2000.080000 ;
    END
    PORT
      LAYER met4 ;
        RECT 398.210000 0.000000 401.310000 3.100000 ;
    END
    PORT
      LAYER met4 ;
        RECT 1533.410000 1996.980000 1536.510000 2000.080000 ;
    END
    PORT
      LAYER met4 ;
        RECT 1533.410000 0.000000 1536.510000 3.100000 ;
    END
    PORT
      LAYER met4 ;
        RECT 372.410000 1996.980000 375.510000 2000.080000 ;
    END
    PORT
      LAYER met4 ;
        RECT 372.410000 0.000000 375.510000 3.100000 ;
    END
    PORT
      LAYER met4 ;
        RECT 1507.610000 1996.980000 1510.710000 2000.080000 ;
    END
    PORT
      LAYER met4 ;
        RECT 1507.610000 0.000000 1510.710000 3.100000 ;
    END
    PORT
      LAYER met4 ;
        RECT 346.610000 1996.980000 349.710000 2000.080000 ;
    END
    PORT
      LAYER met4 ;
        RECT 346.610000 0.000000 349.710000 3.100000 ;
    END
    PORT
      LAYER met4 ;
        RECT 1481.810000 1996.980000 1484.910000 2000.080000 ;
    END
    PORT
      LAYER met4 ;
        RECT 1481.810000 0.000000 1484.910000 3.100000 ;
    END
    PORT
      LAYER met4 ;
        RECT 320.810000 1996.980000 323.910000 2000.080000 ;
    END
    PORT
      LAYER met4 ;
        RECT 320.810000 0.000000 323.910000 3.100000 ;
    END
    PORT
      LAYER met4 ;
        RECT 1456.010000 1996.980000 1459.110000 2000.080000 ;
    END
    PORT
      LAYER met4 ;
        RECT 1456.010000 0.000000 1459.110000 3.100000 ;
    END
    PORT
      LAYER met4 ;
        RECT 295.010000 1996.980000 298.110000 2000.080000 ;
    END
    PORT
      LAYER met4 ;
        RECT 295.010000 0.000000 298.110000 3.100000 ;
    END
    PORT
      LAYER met4 ;
        RECT 1430.210000 1996.980000 1433.310000 2000.080000 ;
    END
    PORT
      LAYER met4 ;
        RECT 1430.210000 0.000000 1433.310000 3.100000 ;
    END
    PORT
      LAYER met4 ;
        RECT 269.210000 1996.980000 272.310000 2000.080000 ;
    END
    PORT
      LAYER met4 ;
        RECT 269.210000 0.000000 272.310000 3.100000 ;
    END
    PORT
      LAYER met4 ;
        RECT 1404.410000 1996.980000 1407.510000 2000.080000 ;
    END
    PORT
      LAYER met4 ;
        RECT 1404.410000 0.000000 1407.510000 3.100000 ;
    END
    PORT
      LAYER met4 ;
        RECT 243.410000 1996.980000 246.510000 2000.080000 ;
    END
    PORT
      LAYER met4 ;
        RECT 243.410000 0.000000 246.510000 3.100000 ;
    END
    PORT
      LAYER met4 ;
        RECT 1378.610000 1996.980000 1381.710000 2000.080000 ;
    END
    PORT
      LAYER met4 ;
        RECT 1378.610000 0.000000 1381.710000 3.100000 ;
    END
    PORT
      LAYER met4 ;
        RECT 217.610000 1996.980000 220.710000 2000.080000 ;
    END
    PORT
      LAYER met4 ;
        RECT 217.610000 0.000000 220.710000 3.100000 ;
    END
    PORT
      LAYER met4 ;
        RECT 1352.810000 1996.980000 1355.910000 2000.080000 ;
    END
    PORT
      LAYER met4 ;
        RECT 1352.810000 0.000000 1355.910000 3.100000 ;
    END
    PORT
      LAYER met4 ;
        RECT 191.810000 1996.980000 194.910000 2000.080000 ;
    END
    PORT
      LAYER met4 ;
        RECT 191.810000 0.000000 194.910000 3.100000 ;
    END
    PORT
      LAYER met4 ;
        RECT 1327.010000 1996.980000 1330.110000 2000.080000 ;
    END
    PORT
      LAYER met4 ;
        RECT 1327.010000 0.000000 1330.110000 3.100000 ;
    END
    PORT
      LAYER met4 ;
        RECT 166.010000 1996.980000 169.110000 2000.080000 ;
    END
    PORT
      LAYER met4 ;
        RECT 166.010000 0.000000 169.110000 3.100000 ;
    END
    PORT
      LAYER met4 ;
        RECT 1301.210000 1996.980000 1304.310000 2000.080000 ;
    END
    PORT
      LAYER met4 ;
        RECT 1301.210000 0.000000 1304.310000 3.100000 ;
    END
    PORT
      LAYER met4 ;
        RECT 140.210000 1996.980000 143.310000 2000.080000 ;
    END
    PORT
      LAYER met4 ;
        RECT 140.210000 0.000000 143.310000 3.100000 ;
    END
    PORT
      LAYER met4 ;
        RECT 1275.410000 1996.980000 1278.510000 2000.080000 ;
    END
    PORT
      LAYER met4 ;
        RECT 1275.410000 0.000000 1278.510000 3.100000 ;
    END
    PORT
      LAYER met4 ;
        RECT 114.410000 1996.980000 117.510000 2000.080000 ;
    END
    PORT
      LAYER met4 ;
        RECT 114.410000 0.000000 117.510000 3.100000 ;
    END
    PORT
      LAYER met4 ;
        RECT 1249.610000 1996.980000 1252.710000 2000.080000 ;
    END
    PORT
      LAYER met4 ;
        RECT 1249.610000 0.000000 1252.710000 3.100000 ;
    END
    PORT
      LAYER met4 ;
        RECT 88.610000 1996.980000 91.710000 2000.080000 ;
    END
    PORT
      LAYER met4 ;
        RECT 88.610000 0.000000 91.710000 3.100000 ;
    END
    PORT
      LAYER met4 ;
        RECT 1223.810000 1996.980000 1226.910000 2000.080000 ;
    END
    PORT
      LAYER met4 ;
        RECT 1223.810000 0.000000 1226.910000 3.100000 ;
    END
    PORT
      LAYER met4 ;
        RECT 62.810000 1996.980000 65.910000 2000.080000 ;
    END
    PORT
      LAYER met4 ;
        RECT 62.810000 0.000000 65.910000 3.100000 ;
    END
    PORT
      LAYER met4 ;
        RECT 1198.010000 1996.980000 1201.110000 2000.080000 ;
    END
    PORT
      LAYER met4 ;
        RECT 1198.010000 0.000000 1201.110000 3.100000 ;
    END
    PORT
      LAYER met4 ;
        RECT 37.010000 1996.980000 40.110000 2000.080000 ;
    END
    PORT
      LAYER met4 ;
        RECT 37.010000 0.000000 40.110000 3.100000 ;
    END
    PORT
      LAYER met4 ;
        RECT 1172.210000 1996.980000 1175.310000 2000.080000 ;
    END
    PORT
      LAYER met4 ;
        RECT 1172.210000 0.000000 1175.310000 3.100000 ;
    END
    PORT
      LAYER met4 ;
        RECT 11.210000 1996.980000 14.310000 2000.080000 ;
    END
    PORT
      LAYER met4 ;
        RECT 11.210000 0.000000 14.310000 3.100000 ;
    END

# P/G power stripe data as pin
    PORT
      LAYER met4 ;
        RECT 88.610000 0.000000 91.710000 2000.080000 ;
        RECT 62.810000 0.000000 65.910000 2000.080000 ;
        RECT 37.010000 0.000000 40.110000 2000.080000 ;
        RECT 11.210000 0.000000 14.310000 2000.080000 ;
        RECT 733.610000 518.540000 736.710000 1498.000000 ;
        RECT 707.810000 518.540000 710.910000 1498.000000 ;
        RECT 682.010000 518.540000 685.110000 1498.000000 ;
        RECT 656.210000 518.540000 659.310000 1498.000000 ;
        RECT 630.410000 518.540000 633.510000 1498.000000 ;
        RECT 604.610000 518.540000 607.710000 1498.000000 ;
        RECT 578.810000 518.540000 581.910000 1498.000000 ;
        RECT 553.010000 518.540000 556.110000 1498.000000 ;
        RECT 527.210000 518.540000 530.310000 1498.000000 ;
        RECT 914.210000 518.540000 917.310000 1498.000000 ;
        RECT 888.410000 518.540000 891.510000 1498.000000 ;
        RECT 862.610000 518.540000 865.710000 1498.000000 ;
        RECT 836.810000 518.540000 839.910000 1498.000000 ;
        RECT 811.010000 518.540000 814.110000 1498.000000 ;
        RECT 785.210000 518.540000 788.310000 1498.000000 ;
        RECT 759.410000 518.540000 762.510000 1498.000000 ;
        RECT 940.010000 518.540000 943.110000 2000.080000 ;
        RECT 991.610000 0.000000 994.710000 2000.080000 ;
        RECT 965.810000 0.000000 968.910000 2000.080000 ;
        RECT 1249.610000 518.540000 1252.710000 1498.000000 ;
        RECT 1223.810000 518.540000 1226.910000 1498.000000 ;
        RECT 1198.010000 518.540000 1201.110000 1498.000000 ;
        RECT 1172.210000 518.540000 1175.310000 1498.000000 ;
        RECT 1146.410000 518.540000 1149.510000 1498.000000 ;
        RECT 1120.610000 518.540000 1123.710000 1498.000000 ;
        RECT 1094.810000 518.540000 1097.910000 1498.000000 ;
        RECT 1069.010000 518.540000 1072.110000 1498.000000 ;
        RECT 1043.210000 518.540000 1046.310000 2000.080000 ;
        RECT 1017.410000 0.000000 1020.510000 2000.080000 ;
        RECT 1481.810000 518.540000 1484.910000 1498.000000 ;
        RECT 1456.010000 518.540000 1459.110000 1498.000000 ;
        RECT 1430.210000 518.540000 1433.310000 1498.000000 ;
        RECT 1404.410000 518.540000 1407.510000 1498.000000 ;
        RECT 1378.610000 518.540000 1381.710000 1498.000000 ;
        RECT 1352.810000 518.540000 1355.910000 1498.000000 ;
        RECT 1327.010000 518.540000 1330.110000 1498.000000 ;
        RECT 1301.210000 518.540000 1304.310000 1498.000000 ;
        RECT 1275.410000 518.540000 1278.510000 1498.000000 ;
        RECT 1972.010000 0.000000 1975.110000 2000.080000 ;
        RECT 1946.210000 0.000000 1949.310000 2000.080000 ;
        RECT 1920.410000 0.000000 1923.510000 2000.080000 ;
        RECT 243.410000 0.000000 246.510000 577.220000 ;
        RECT 217.610000 0.000000 220.710000 577.220000 ;
        RECT 191.810000 0.000000 194.910000 577.220000 ;
        RECT 166.010000 0.000000 169.110000 577.220000 ;
        RECT 140.210000 0.000000 143.310000 577.220000 ;
        RECT 114.410000 0.000000 117.510000 577.220000 ;
        RECT 372.410000 0.000000 375.510000 98.000000 ;
        RECT 346.610000 0.000000 349.710000 98.000000 ;
        RECT 320.810000 0.000000 323.910000 98.000000 ;
        RECT 295.010000 0.000000 298.110000 98.000000 ;
        RECT 269.210000 0.000000 272.310000 98.000000 ;
        RECT 475.610000 0.000000 478.710000 98.000000 ;
        RECT 449.810000 0.000000 452.910000 98.000000 ;
        RECT 424.010000 0.000000 427.110000 98.000000 ;
        RECT 398.210000 0.000000 401.310000 98.000000 ;
        RECT 604.610000 0.000000 607.710000 98.000000 ;
        RECT 578.810000 0.000000 581.910000 98.000000 ;
        RECT 553.010000 0.000000 556.110000 98.000000 ;
        RECT 527.210000 0.000000 530.310000 98.000000 ;
        RECT 501.410000 0.000000 504.510000 98.000000 ;
        RECT 733.610000 0.000000 736.710000 98.000000 ;
        RECT 707.810000 0.000000 710.910000 98.000000 ;
        RECT 682.010000 0.000000 685.110000 98.000000 ;
        RECT 656.210000 0.000000 659.310000 98.000000 ;
        RECT 630.410000 0.000000 633.510000 98.000000 ;
        RECT 862.610000 0.000000 865.710000 98.000000 ;
        RECT 836.810000 0.000000 839.910000 98.000000 ;
        RECT 811.010000 0.000000 814.110000 98.000000 ;
        RECT 785.210000 0.000000 788.310000 98.000000 ;
        RECT 759.410000 0.000000 762.510000 98.000000 ;
        RECT 940.010000 0.000000 943.110000 98.000000 ;
        RECT 914.210000 0.000000 917.310000 98.000000 ;
        RECT 888.410000 0.000000 891.510000 98.000000 ;
        RECT 372.410000 518.540000 375.510000 577.220000 ;
        RECT 346.610000 518.540000 349.710000 577.220000 ;
        RECT 320.810000 518.540000 323.910000 577.220000 ;
        RECT 295.010000 518.540000 298.110000 577.220000 ;
        RECT 269.210000 518.540000 272.310000 577.220000 ;
        RECT 475.610000 518.540000 478.710000 577.220000 ;
        RECT 449.810000 518.540000 452.910000 577.220000 ;
        RECT 424.010000 518.540000 427.110000 577.220000 ;
        RECT 398.210000 518.540000 401.310000 577.220000 ;
        RECT 501.410000 518.540000 504.510000 577.220000 ;
        RECT 1894.610000 0.000000 1897.710000 577.220000 ;
        RECT 1868.810000 0.000000 1871.910000 577.220000 ;
        RECT 1843.010000 0.000000 1846.110000 577.220000 ;
        RECT 1817.210000 0.000000 1820.310000 577.220000 ;
        RECT 1791.410000 0.000000 1794.510000 577.220000 ;
        RECT 1765.610000 0.000000 1768.710000 577.220000 ;
        RECT 1739.810000 0.000000 1742.910000 577.220000 ;
        RECT 1714.010000 0.000000 1717.110000 577.220000 ;
        RECT 1249.610000 0.000000 1252.710000 98.000000 ;
        RECT 1120.610000 0.000000 1123.710000 98.000000 ;
        RECT 1094.810000 0.000000 1097.910000 98.000000 ;
        RECT 1069.010000 0.000000 1072.110000 98.000000 ;
        RECT 1043.210000 0.000000 1046.310000 98.000000 ;
        RECT 1223.810000 0.000000 1226.910000 98.000000 ;
        RECT 1198.010000 0.000000 1201.110000 98.000000 ;
        RECT 1172.210000 0.000000 1175.310000 98.000000 ;
        RECT 1146.410000 0.000000 1149.510000 98.000000 ;
        RECT 1352.810000 0.000000 1355.910000 98.000000 ;
        RECT 1327.010000 0.000000 1330.110000 98.000000 ;
        RECT 1301.210000 0.000000 1304.310000 98.000000 ;
        RECT 1275.410000 0.000000 1278.510000 98.000000 ;
        RECT 1481.810000 0.000000 1484.910000 98.000000 ;
        RECT 1456.010000 0.000000 1459.110000 98.000000 ;
        RECT 1430.210000 0.000000 1433.310000 98.000000 ;
        RECT 1404.410000 0.000000 1407.510000 98.000000 ;
        RECT 1378.610000 0.000000 1381.710000 98.000000 ;
        RECT 1610.810000 0.000000 1613.910000 98.000000 ;
        RECT 1585.010000 0.000000 1588.110000 98.000000 ;
        RECT 1559.210000 0.000000 1562.310000 98.000000 ;
        RECT 1533.410000 0.000000 1536.510000 98.000000 ;
        RECT 1507.610000 0.000000 1510.710000 98.000000 ;
        RECT 1688.210000 0.000000 1691.310000 98.000000 ;
        RECT 1662.410000 0.000000 1665.510000 98.000000 ;
        RECT 1636.610000 0.000000 1639.710000 98.000000 ;
        RECT 1610.810000 518.540000 1613.910000 577.220000 ;
        RECT 1585.010000 518.540000 1588.110000 577.220000 ;
        RECT 1559.210000 518.540000 1562.310000 577.220000 ;
        RECT 1533.410000 518.540000 1536.510000 577.220000 ;
        RECT 1507.610000 518.540000 1510.710000 577.220000 ;
        RECT 1688.210000 518.540000 1691.310000 577.220000 ;
        RECT 1662.410000 518.540000 1665.510000 577.220000 ;
        RECT 1636.610000 518.540000 1639.710000 577.220000 ;
        RECT 243.410000 1265.100000 246.510000 2000.080000 ;
        RECT 217.610000 1265.100000 220.710000 2000.080000 ;
        RECT 191.810000 1265.100000 194.910000 2000.080000 ;
        RECT 166.010000 1265.100000 169.110000 2000.080000 ;
        RECT 140.210000 1265.100000 143.310000 2000.080000 ;
        RECT 114.410000 1265.100000 117.510000 2000.080000 ;
        RECT 475.610000 1265.100000 478.710000 1498.000000 ;
        RECT 449.810000 1265.100000 452.910000 1498.000000 ;
        RECT 424.010000 1265.100000 427.110000 1498.000000 ;
        RECT 398.210000 1265.100000 401.310000 1498.000000 ;
        RECT 372.410000 1265.100000 375.510000 1498.000000 ;
        RECT 346.610000 1265.100000 349.710000 1498.000000 ;
        RECT 320.810000 1265.100000 323.910000 1498.000000 ;
        RECT 295.010000 1265.100000 298.110000 1498.000000 ;
        RECT 269.210000 1265.100000 272.310000 1498.000000 ;
        RECT 501.410000 1265.100000 504.510000 1498.000000 ;
        RECT 372.410000 1918.540000 375.510000 2000.080000 ;
        RECT 346.610000 1918.540000 349.710000 2000.080000 ;
        RECT 320.810000 1918.540000 323.910000 2000.080000 ;
        RECT 295.010000 1918.540000 298.110000 2000.080000 ;
        RECT 269.210000 1918.540000 272.310000 2000.080000 ;
        RECT 475.610000 1918.540000 478.710000 2000.080000 ;
        RECT 449.810000 1918.540000 452.910000 2000.080000 ;
        RECT 424.010000 1918.540000 427.110000 2000.080000 ;
        RECT 398.210000 1918.540000 401.310000 2000.080000 ;
        RECT 604.610000 1918.540000 607.710000 2000.080000 ;
        RECT 578.810000 1918.540000 581.910000 2000.080000 ;
        RECT 553.010000 1918.540000 556.110000 2000.080000 ;
        RECT 527.210000 1918.540000 530.310000 2000.080000 ;
        RECT 501.410000 1918.540000 504.510000 2000.080000 ;
        RECT 733.610000 1918.540000 736.710000 2000.080000 ;
        RECT 707.810000 1918.540000 710.910000 2000.080000 ;
        RECT 682.010000 1918.540000 685.110000 2000.080000 ;
        RECT 656.210000 1918.540000 659.310000 2000.080000 ;
        RECT 630.410000 1918.540000 633.510000 2000.080000 ;
        RECT 862.610000 1918.540000 865.710000 2000.080000 ;
        RECT 836.810000 1918.540000 839.910000 2000.080000 ;
        RECT 811.010000 1918.540000 814.110000 2000.080000 ;
        RECT 785.210000 1918.540000 788.310000 2000.080000 ;
        RECT 759.410000 1918.540000 762.510000 2000.080000 ;
        RECT 914.210000 1918.540000 917.310000 2000.080000 ;
        RECT 888.410000 1918.540000 891.510000 2000.080000 ;
        RECT 1894.610000 1265.100000 1897.710000 2000.080000 ;
        RECT 1868.810000 1265.100000 1871.910000 2000.080000 ;
        RECT 1843.010000 1265.100000 1846.110000 2000.080000 ;
        RECT 1817.210000 1265.100000 1820.310000 2000.080000 ;
        RECT 1791.410000 1265.100000 1794.510000 2000.080000 ;
        RECT 1765.610000 1265.100000 1768.710000 2000.080000 ;
        RECT 1739.810000 1265.100000 1742.910000 2000.080000 ;
        RECT 1714.010000 1265.100000 1717.110000 1498.000000 ;
        RECT 1688.210000 1265.100000 1691.310000 1498.000000 ;
        RECT 1662.410000 1265.100000 1665.510000 1498.000000 ;
        RECT 1636.610000 1265.100000 1639.710000 1498.000000 ;
        RECT 1610.810000 1265.100000 1613.910000 1498.000000 ;
        RECT 1585.010000 1265.100000 1588.110000 1498.000000 ;
        RECT 1559.210000 1265.100000 1562.310000 1498.000000 ;
        RECT 1533.410000 1265.100000 1536.510000 1498.000000 ;
        RECT 1507.610000 1265.100000 1510.710000 1498.000000 ;
        RECT 1249.610000 1918.540000 1252.710000 2000.080000 ;
        RECT 1120.610000 1918.540000 1123.710000 2000.080000 ;
        RECT 1094.810000 1918.540000 1097.910000 2000.080000 ;
        RECT 1069.010000 1918.540000 1072.110000 2000.080000 ;
        RECT 1223.810000 1918.540000 1226.910000 2000.080000 ;
        RECT 1198.010000 1918.540000 1201.110000 2000.080000 ;
        RECT 1172.210000 1918.540000 1175.310000 2000.080000 ;
        RECT 1146.410000 1918.540000 1149.510000 2000.080000 ;
        RECT 1352.810000 1918.540000 1355.910000 2000.080000 ;
        RECT 1327.010000 1918.540000 1330.110000 2000.080000 ;
        RECT 1301.210000 1918.540000 1304.310000 2000.080000 ;
        RECT 1275.410000 1918.540000 1278.510000 2000.080000 ;
        RECT 1481.810000 1918.540000 1484.910000 2000.080000 ;
        RECT 1456.010000 1918.540000 1459.110000 2000.080000 ;
        RECT 1430.210000 1918.540000 1433.310000 2000.080000 ;
        RECT 1404.410000 1918.540000 1407.510000 2000.080000 ;
        RECT 1378.610000 1918.540000 1381.710000 2000.080000 ;
        RECT 1610.810000 1918.540000 1613.910000 2000.080000 ;
        RECT 1585.010000 1918.540000 1588.110000 2000.080000 ;
        RECT 1559.210000 1918.540000 1562.310000 2000.080000 ;
        RECT 1533.410000 1918.540000 1536.510000 2000.080000 ;
        RECT 1507.610000 1918.540000 1510.710000 2000.080000 ;
        RECT 1714.010000 1918.540000 1717.110000 2000.080000 ;
        RECT 1688.210000 1918.540000 1691.310000 2000.080000 ;
        RECT 1662.410000 1918.540000 1665.510000 2000.080000 ;
        RECT 1636.610000 1918.540000 1639.710000 2000.080000 ;
    END
# end of P/G power stripe data as pin

  END vccd1
  OBS
    LAYER li1 ;
      RECT 0.000000 0.000000 2000.080000 2000.080000 ;
    LAYER met1 ;
      RECT 0.000000 0.000000 2000.080000 2000.080000 ;
    LAYER met2 ;
      RECT 1986.400000 1999.315000 2000.080000 2000.080000 ;
      RECT 1914.180000 1999.315000 1985.700000 2000.080000 ;
      RECT 1854.840000 1999.315000 1913.480000 2000.080000 ;
      RECT 1783.080000 1999.315000 1854.140000 2000.080000 ;
      RECT 1723.280000 1999.315000 1782.380000 2000.080000 ;
      RECT 1652.440000 1999.315000 1722.580000 2000.080000 ;
      RECT 1591.720000 1999.315000 1651.740000 2000.080000 ;
      RECT 1521.800000 1999.315000 1591.020000 2000.080000 ;
      RECT 1460.160000 1999.315000 1521.100000 2000.080000 ;
      RECT 1390.700000 1999.315000 1459.460000 2000.080000 ;
      RECT 1329.060000 1999.315000 1390.000000 2000.080000 ;
      RECT 1260.060000 1999.315000 1328.360000 2000.080000 ;
      RECT 1197.500000 1999.315000 1259.360000 2000.080000 ;
      RECT 1129.420000 1999.315000 1196.800000 2000.080000 ;
      RECT 1064.560000 1999.315000 1128.720000 2000.080000 ;
      RECT 998.320000 1999.315000 1063.860000 2000.080000 ;
      RECT 934.380000 1999.315000 997.620000 2000.080000 ;
      RECT 867.680000 1999.315000 933.680000 2000.080000 ;
      RECT 802.820000 1999.315000 866.980000 2000.080000 ;
      RECT 736.580000 1999.315000 802.120000 2000.080000 ;
      RECT 671.260000 1999.315000 735.880000 2000.080000 ;
      RECT 605.940000 1999.315000 670.560000 2000.080000 ;
      RECT 540.160000 1999.315000 605.240000 2000.080000 ;
      RECT 475.300000 1999.315000 539.460000 2000.080000 ;
      RECT 408.600000 1999.315000 474.600000 2000.080000 ;
      RECT 342.360000 1999.315000 407.900000 2000.080000 ;
      RECT 277.040000 1999.315000 341.660000 2000.080000 ;
      RECT 213.100000 1999.315000 276.340000 2000.080000 ;
      RECT 145.480000 1999.315000 212.400000 2000.080000 ;
      RECT 82.920000 1999.315000 144.780000 2000.080000 ;
      RECT 13.920000 1999.315000 82.220000 2000.080000 ;
      RECT 0.000000 1999.315000 13.220000 2000.080000 ;
      RECT 0.000000 0.765000 2000.080000 1999.315000 ;
      RECT 0.580000 0.000000 1999.500000 0.765000 ;
    LAYER met3 ;
      RECT 0.000000 1941.470000 2000.080000 2000.080000 ;
      RECT 0.000000 1940.370000 1998.880000 1941.470000 ;
      RECT 0.000000 1935.980000 2000.080000 1940.370000 ;
      RECT 1.200000 1934.880000 2000.080000 1935.980000 ;
      RECT 0.000000 1845.090000 2000.080000 1934.880000 ;
      RECT 0.000000 1844.480000 1998.880000 1845.090000 ;
      RECT 1.200000 1843.990000 1998.880000 1844.480000 ;
      RECT 1.200000 1843.380000 2000.080000 1843.990000 ;
      RECT 0.000000 1767.620000 2000.080000 1843.380000 ;
      RECT 0.000000 1766.520000 1998.880000 1767.620000 ;
      RECT 0.000000 1762.740000 2000.080000 1766.520000 ;
      RECT 1.200000 1761.640000 2000.080000 1762.740000 ;
      RECT 0.000000 1670.630000 2000.080000 1761.640000 ;
      RECT 0.000000 1670.020000 1998.880000 1670.630000 ;
      RECT 1.200000 1669.530000 1998.880000 1670.020000 ;
      RECT 1.200000 1668.920000 2000.080000 1669.530000 ;
      RECT 0.000000 1594.380000 2000.080000 1668.920000 ;
      RECT 0.000000 1593.280000 1998.880000 1594.380000 ;
      RECT 0.000000 1588.890000 2000.080000 1593.280000 ;
      RECT 1.200000 1587.790000 2000.080000 1588.890000 ;
      RECT 0.000000 1496.170000 2000.080000 1587.790000 ;
      RECT 0.000000 1495.560000 1998.880000 1496.170000 ;
      RECT 1.200000 1495.070000 1998.880000 1495.560000 ;
      RECT 1.200000 1494.460000 2000.080000 1495.070000 ;
      RECT 0.000000 1421.140000 2000.080000 1494.460000 ;
      RECT 0.000000 1420.040000 1998.880000 1421.140000 ;
      RECT 0.000000 1415.650000 2000.080000 1420.040000 ;
      RECT 1.200000 1414.550000 2000.080000 1415.650000 ;
      RECT 0.000000 1321.710000 2000.080000 1414.550000 ;
      RECT 0.000000 1321.100000 1998.880000 1321.710000 ;
      RECT 1.200000 1320.610000 1998.880000 1321.100000 ;
      RECT 1.200000 1320.000000 2000.080000 1320.610000 ;
      RECT 0.000000 1247.290000 2000.080000 1320.000000 ;
      RECT 0.000000 1246.190000 1998.880000 1247.290000 ;
      RECT 0.000000 1242.410000 2000.080000 1246.190000 ;
      RECT 1.200000 1241.310000 2000.080000 1242.410000 ;
      RECT 0.000000 1147.250000 2000.080000 1241.310000 ;
      RECT 0.000000 1146.640000 1998.880000 1147.250000 ;
      RECT 1.200000 1146.150000 1998.880000 1146.640000 ;
      RECT 1.200000 1145.540000 2000.080000 1146.150000 ;
      RECT 0.000000 1074.050000 2000.080000 1145.540000 ;
      RECT 0.000000 1072.950000 1998.880000 1074.050000 ;
      RECT 0.000000 1068.560000 2000.080000 1072.950000 ;
      RECT 1.200000 1067.460000 2000.080000 1068.560000 ;
      RECT 0.000000 973.400000 2000.080000 1067.460000 ;
      RECT 0.000000 972.790000 1998.880000 973.400000 ;
      RECT 1.200000 972.300000 1998.880000 972.790000 ;
      RECT 1.200000 971.690000 2000.080000 972.300000 ;
      RECT 0.000000 900.810000 2000.080000 971.690000 ;
      RECT 0.000000 899.710000 1998.880000 900.810000 ;
      RECT 0.000000 895.320000 2000.080000 899.710000 ;
      RECT 1.200000 894.220000 2000.080000 895.320000 ;
      RECT 0.000000 798.940000 2000.080000 894.220000 ;
      RECT 0.000000 798.330000 1998.880000 798.940000 ;
      RECT 1.200000 797.840000 1998.880000 798.330000 ;
      RECT 1.200000 797.230000 2000.080000 797.840000 ;
      RECT 0.000000 722.080000 2000.080000 797.230000 ;
      RECT 1.200000 720.980000 2000.080000 722.080000 ;
      RECT 0.000000 624.480000 2000.080000 720.980000 ;
      RECT 0.000000 623.870000 1998.880000 624.480000 ;
      RECT 1.200000 623.380000 1998.880000 623.870000 ;
      RECT 1.200000 622.770000 2000.080000 623.380000 ;
      RECT 0.000000 548.230000 2000.080000 622.770000 ;
      RECT 1.200000 547.130000 2000.080000 548.230000 ;
      RECT 0.000000 450.020000 2000.080000 547.130000 ;
      RECT 0.000000 449.410000 1998.880000 450.020000 ;
      RECT 1.200000 448.920000 1998.880000 449.410000 ;
      RECT 1.200000 448.310000 2000.080000 448.920000 ;
      RECT 0.000000 374.990000 2000.080000 448.310000 ;
      RECT 1.200000 373.890000 2000.080000 374.990000 ;
      RECT 0.000000 275.560000 2000.080000 373.890000 ;
      RECT 0.000000 274.950000 1998.880000 275.560000 ;
      RECT 1.200000 274.460000 1998.880000 274.950000 ;
      RECT 1.200000 273.850000 2000.080000 274.460000 ;
      RECT 0.000000 201.140000 2000.080000 273.850000 ;
      RECT 1.200000 200.040000 2000.080000 201.140000 ;
      RECT 0.000000 101.710000 2000.080000 200.040000 ;
      RECT 0.000000 101.100000 1998.880000 101.710000 ;
      RECT 1.200000 100.610000 1998.880000 101.100000 ;
      RECT 1.200000 100.000000 2000.080000 100.610000 ;
      RECT 0.000000 0.000000 2000.080000 100.000000 ;
    LAYER met4 ;
      RECT 1717.510000 1918.140000 1735.210000 2000.080000 ;
      RECT 1713.310000 1918.140000 1713.610000 2000.080000 ;
      RECT 1691.710000 1918.140000 1709.410000 2000.080000 ;
      RECT 1687.510000 1918.140000 1687.810000 2000.080000 ;
      RECT 1665.910000 1918.140000 1683.610000 2000.080000 ;
      RECT 1661.710000 1918.140000 1662.010000 2000.080000 ;
      RECT 1640.110000 1918.140000 1657.810000 2000.080000 ;
      RECT 1635.910000 1918.140000 1636.210000 2000.080000 ;
      RECT 1614.310000 1918.140000 1632.010000 2000.080000 ;
      RECT 1610.110000 1918.140000 1610.410000 2000.080000 ;
      RECT 1588.510000 1918.140000 1606.210000 2000.080000 ;
      RECT 1584.310000 1918.140000 1584.610000 2000.080000 ;
      RECT 1562.710000 1918.140000 1580.410000 2000.080000 ;
      RECT 1558.510000 1918.140000 1558.810000 2000.080000 ;
      RECT 1536.910000 1918.140000 1554.610000 2000.080000 ;
      RECT 1532.710000 1918.140000 1533.010000 2000.080000 ;
      RECT 1511.110000 1918.140000 1528.810000 2000.080000 ;
      RECT 1506.910000 1918.140000 1507.210000 2000.080000 ;
      RECT 1485.310000 1918.140000 1503.010000 2000.080000 ;
      RECT 1481.110000 1918.140000 1481.410000 2000.080000 ;
      RECT 1459.510000 1918.140000 1477.210000 2000.080000 ;
      RECT 1455.310000 1918.140000 1455.610000 2000.080000 ;
      RECT 1433.710000 1918.140000 1451.410000 2000.080000 ;
      RECT 1429.510000 1918.140000 1429.810000 2000.080000 ;
      RECT 1407.910000 1918.140000 1425.610000 2000.080000 ;
      RECT 1403.710000 1918.140000 1404.010000 2000.080000 ;
      RECT 1382.110000 1918.140000 1399.810000 2000.080000 ;
      RECT 1377.910000 1918.140000 1378.210000 2000.080000 ;
      RECT 1356.310000 1918.140000 1374.010000 2000.080000 ;
      RECT 1352.110000 1918.140000 1352.410000 2000.080000 ;
      RECT 1330.510000 1918.140000 1348.210000 2000.080000 ;
      RECT 1326.310000 1918.140000 1326.610000 2000.080000 ;
      RECT 1304.710000 1918.140000 1322.410000 2000.080000 ;
      RECT 1300.510000 1918.140000 1300.810000 2000.080000 ;
      RECT 1278.910000 1918.140000 1296.610000 2000.080000 ;
      RECT 1274.710000 1918.140000 1275.010000 2000.080000 ;
      RECT 1253.110000 1918.140000 1270.810000 2000.080000 ;
      RECT 1248.910000 1918.140000 1249.210000 2000.080000 ;
      RECT 1227.310000 1918.140000 1245.010000 2000.080000 ;
      RECT 1223.110000 1918.140000 1223.410000 2000.080000 ;
      RECT 1201.510000 1918.140000 1219.210000 2000.080000 ;
      RECT 1197.310000 1918.140000 1197.610000 2000.080000 ;
      RECT 1175.710000 1918.140000 1193.410000 2000.080000 ;
      RECT 1171.510000 1918.140000 1171.810000 2000.080000 ;
      RECT 1149.910000 1918.140000 1167.610000 2000.080000 ;
      RECT 1145.710000 1918.140000 1146.010000 2000.080000 ;
      RECT 1124.110000 1918.140000 1141.810000 2000.080000 ;
      RECT 1119.910000 1918.140000 1120.210000 2000.080000 ;
      RECT 1098.310000 1918.140000 1116.010000 2000.080000 ;
      RECT 1094.110000 1918.140000 1094.410000 2000.080000 ;
      RECT 1072.510000 1918.140000 1090.210000 2000.080000 ;
      RECT 1068.310000 1918.140000 1068.610000 2000.080000 ;
      RECT 1046.710000 1918.140000 1064.410000 2000.080000 ;
      RECT 917.710000 1918.140000 935.410000 2000.080000 ;
      RECT 913.510000 1918.140000 913.810000 2000.080000 ;
      RECT 891.910000 1918.140000 909.610000 2000.080000 ;
      RECT 887.710000 1918.140000 888.010000 2000.080000 ;
      RECT 866.110000 1918.140000 883.810000 2000.080000 ;
      RECT 861.910000 1918.140000 862.210000 2000.080000 ;
      RECT 840.310000 1918.140000 858.010000 2000.080000 ;
      RECT 836.110000 1918.140000 836.410000 2000.080000 ;
      RECT 814.510000 1918.140000 832.210000 2000.080000 ;
      RECT 810.310000 1918.140000 810.610000 2000.080000 ;
      RECT 788.710000 1918.140000 806.410000 2000.080000 ;
      RECT 784.510000 1918.140000 784.810000 2000.080000 ;
      RECT 762.910000 1918.140000 780.610000 2000.080000 ;
      RECT 758.710000 1918.140000 759.010000 2000.080000 ;
      RECT 737.110000 1918.140000 754.810000 2000.080000 ;
      RECT 732.910000 1918.140000 733.210000 2000.080000 ;
      RECT 711.310000 1918.140000 729.010000 2000.080000 ;
      RECT 707.110000 1918.140000 707.410000 2000.080000 ;
      RECT 685.510000 1918.140000 703.210000 2000.080000 ;
      RECT 681.310000 1918.140000 681.610000 2000.080000 ;
      RECT 659.710000 1918.140000 677.410000 2000.080000 ;
      RECT 655.510000 1918.140000 655.810000 2000.080000 ;
      RECT 633.910000 1918.140000 651.610000 2000.080000 ;
      RECT 629.710000 1918.140000 630.010000 2000.080000 ;
      RECT 608.110000 1918.140000 625.810000 2000.080000 ;
      RECT 603.910000 1918.140000 604.210000 2000.080000 ;
      RECT 582.310000 1918.140000 600.010000 2000.080000 ;
      RECT 578.110000 1918.140000 578.410000 2000.080000 ;
      RECT 556.510000 1918.140000 574.210000 2000.080000 ;
      RECT 552.310000 1918.140000 552.610000 2000.080000 ;
      RECT 530.710000 1918.140000 548.410000 2000.080000 ;
      RECT 526.510000 1918.140000 526.810000 2000.080000 ;
      RECT 504.910000 1918.140000 522.610000 2000.080000 ;
      RECT 500.710000 1918.140000 501.010000 2000.080000 ;
      RECT 479.110000 1918.140000 496.810000 2000.080000 ;
      RECT 474.910000 1918.140000 475.210000 2000.080000 ;
      RECT 453.310000 1918.140000 471.010000 2000.080000 ;
      RECT 449.110000 1918.140000 449.410000 2000.080000 ;
      RECT 427.510000 1918.140000 445.210000 2000.080000 ;
      RECT 423.310000 1918.140000 423.610000 2000.080000 ;
      RECT 401.710000 1918.140000 419.410000 2000.080000 ;
      RECT 397.510000 1918.140000 397.810000 2000.080000 ;
      RECT 375.910000 1918.140000 393.610000 2000.080000 ;
      RECT 371.710000 1918.140000 372.010000 2000.080000 ;
      RECT 350.110000 1918.140000 367.810000 2000.080000 ;
      RECT 345.910000 1918.140000 346.210000 2000.080000 ;
      RECT 324.310000 1918.140000 342.010000 2000.080000 ;
      RECT 320.110000 1918.140000 320.410000 2000.080000 ;
      RECT 298.510000 1918.140000 316.210000 2000.080000 ;
      RECT 294.310000 1918.140000 294.610000 2000.080000 ;
      RECT 272.710000 1918.140000 290.410000 2000.080000 ;
      RECT 268.510000 1918.140000 268.810000 2000.080000 ;
      RECT 246.910000 1918.140000 264.610000 2000.080000 ;
      RECT 1046.710000 1498.400000 1735.210000 1918.140000 ;
      RECT 246.910000 1498.400000 935.410000 1918.140000 ;
      RECT 1898.110000 1264.700000 1915.810000 2000.080000 ;
      RECT 1893.910000 1264.700000 1894.210000 2000.080000 ;
      RECT 1872.310000 1264.700000 1890.010000 2000.080000 ;
      RECT 1868.110000 1264.700000 1868.410000 2000.080000 ;
      RECT 1846.510000 1264.700000 1864.210000 2000.080000 ;
      RECT 1842.310000 1264.700000 1842.610000 2000.080000 ;
      RECT 1820.710000 1264.700000 1838.410000 2000.080000 ;
      RECT 1816.510000 1264.700000 1816.810000 2000.080000 ;
      RECT 1794.910000 1264.700000 1812.610000 2000.080000 ;
      RECT 1790.710000 1264.700000 1791.010000 2000.080000 ;
      RECT 1769.110000 1264.700000 1786.810000 2000.080000 ;
      RECT 1764.910000 1264.700000 1765.210000 2000.080000 ;
      RECT 1743.310000 1264.700000 1761.010000 2000.080000 ;
      RECT 1739.110000 1264.700000 1739.410000 2000.080000 ;
      RECT 1717.510000 1264.700000 1735.210000 1498.400000 ;
      RECT 1713.310000 1264.700000 1713.610000 1498.400000 ;
      RECT 1691.710000 1264.700000 1709.410000 1498.400000 ;
      RECT 1687.510000 1264.700000 1687.810000 1498.400000 ;
      RECT 1665.910000 1264.700000 1683.610000 1498.400000 ;
      RECT 1661.710000 1264.700000 1662.010000 1498.400000 ;
      RECT 1640.110000 1264.700000 1657.810000 1498.400000 ;
      RECT 1635.910000 1264.700000 1636.210000 1498.400000 ;
      RECT 1614.310000 1264.700000 1632.010000 1498.400000 ;
      RECT 1610.110000 1264.700000 1610.410000 1498.400000 ;
      RECT 1588.510000 1264.700000 1606.210000 1498.400000 ;
      RECT 1584.310000 1264.700000 1584.610000 1498.400000 ;
      RECT 1562.710000 1264.700000 1580.410000 1498.400000 ;
      RECT 1558.510000 1264.700000 1558.810000 1498.400000 ;
      RECT 1536.910000 1264.700000 1554.610000 1498.400000 ;
      RECT 1532.710000 1264.700000 1533.010000 1498.400000 ;
      RECT 1511.110000 1264.700000 1528.810000 1498.400000 ;
      RECT 1506.910000 1264.700000 1507.210000 1498.400000 ;
      RECT 504.910000 1264.700000 522.610000 1498.400000 ;
      RECT 500.710000 1264.700000 501.010000 1498.400000 ;
      RECT 479.110000 1264.700000 496.810000 1498.400000 ;
      RECT 474.910000 1264.700000 475.210000 1498.400000 ;
      RECT 453.310000 1264.700000 471.010000 1498.400000 ;
      RECT 449.110000 1264.700000 449.410000 1498.400000 ;
      RECT 427.510000 1264.700000 445.210000 1498.400000 ;
      RECT 423.310000 1264.700000 423.610000 1498.400000 ;
      RECT 401.710000 1264.700000 419.410000 1498.400000 ;
      RECT 397.510000 1264.700000 397.810000 1498.400000 ;
      RECT 375.910000 1264.700000 393.610000 1498.400000 ;
      RECT 371.710000 1264.700000 372.010000 1498.400000 ;
      RECT 350.110000 1264.700000 367.810000 1498.400000 ;
      RECT 345.910000 1264.700000 346.210000 1498.400000 ;
      RECT 324.310000 1264.700000 342.010000 1498.400000 ;
      RECT 320.110000 1264.700000 320.410000 1498.400000 ;
      RECT 298.510000 1264.700000 316.210000 1498.400000 ;
      RECT 294.310000 1264.700000 294.610000 1498.400000 ;
      RECT 272.710000 1264.700000 290.410000 1498.400000 ;
      RECT 268.510000 1264.700000 268.810000 1498.400000 ;
      RECT 246.910000 1264.700000 264.610000 1498.400000 ;
      RECT 242.710000 1264.700000 243.010000 2000.080000 ;
      RECT 221.110000 1264.700000 238.810000 2000.080000 ;
      RECT 216.910000 1264.700000 217.210000 2000.080000 ;
      RECT 195.310000 1264.700000 213.010000 2000.080000 ;
      RECT 191.110000 1264.700000 191.410000 2000.080000 ;
      RECT 169.510000 1264.700000 187.210000 2000.080000 ;
      RECT 165.310000 1264.700000 165.610000 2000.080000 ;
      RECT 143.710000 1264.700000 161.410000 2000.080000 ;
      RECT 139.510000 1264.700000 139.810000 2000.080000 ;
      RECT 117.910000 1264.700000 135.610000 2000.080000 ;
      RECT 113.710000 1264.700000 114.010000 2000.080000 ;
      RECT 1919.710000 1264.650000 1920.010000 2000.080000 ;
      RECT 1893.910000 1264.650000 1915.810000 1264.700000 ;
      RECT 1868.110000 1264.650000 1890.010000 1264.700000 ;
      RECT 1842.310000 1264.650000 1864.210000 1264.700000 ;
      RECT 1816.510000 1264.650000 1838.410000 1264.700000 ;
      RECT 1790.710000 1264.650000 1812.610000 1264.700000 ;
      RECT 1764.910000 1264.650000 1786.810000 1264.700000 ;
      RECT 1739.110000 1264.650000 1761.010000 1264.700000 ;
      RECT 1713.310000 1264.650000 1735.210000 1264.700000 ;
      RECT 1687.510000 1264.650000 1709.410000 1264.700000 ;
      RECT 1661.710000 1264.650000 1683.610000 1264.700000 ;
      RECT 1635.910000 1264.650000 1657.810000 1264.700000 ;
      RECT 1610.110000 1264.650000 1632.010000 1264.700000 ;
      RECT 1584.310000 1264.650000 1606.210000 1264.700000 ;
      RECT 1558.510000 1264.650000 1580.410000 1264.700000 ;
      RECT 1532.710000 1264.650000 1554.610000 1264.700000 ;
      RECT 1506.910000 1264.650000 1528.810000 1264.700000 ;
      RECT 1485.310000 1264.650000 1503.010000 1498.400000 ;
      RECT 500.710000 1264.650000 522.610000 1264.700000 ;
      RECT 474.910000 1264.650000 496.810000 1264.700000 ;
      RECT 449.110000 1264.650000 471.010000 1264.700000 ;
      RECT 423.310000 1264.650000 445.210000 1264.700000 ;
      RECT 397.510000 1264.650000 419.410000 1264.700000 ;
      RECT 371.710000 1264.650000 393.610000 1264.700000 ;
      RECT 345.910000 1264.650000 367.810000 1264.700000 ;
      RECT 320.110000 1264.650000 342.010000 1264.700000 ;
      RECT 294.310000 1264.650000 316.210000 1264.700000 ;
      RECT 268.510000 1264.650000 290.410000 1264.700000 ;
      RECT 242.710000 1264.650000 264.610000 1264.700000 ;
      RECT 216.910000 1264.650000 238.810000 1264.700000 ;
      RECT 191.110000 1264.650000 213.010000 1264.700000 ;
      RECT 165.310000 1264.650000 187.210000 1264.700000 ;
      RECT 139.510000 1264.650000 161.410000 1264.700000 ;
      RECT 113.710000 1264.650000 135.610000 1264.700000 ;
      RECT 92.110000 1264.650000 109.810000 2000.080000 ;
      RECT 1485.310000 578.400000 1920.010000 1264.650000 ;
      RECT 92.110000 578.400000 522.610000 1264.650000 ;
      RECT 1893.910000 577.620000 1915.810000 578.400000 ;
      RECT 1868.110000 577.620000 1890.010000 578.400000 ;
      RECT 1842.310000 577.620000 1864.210000 578.400000 ;
      RECT 1816.510000 577.620000 1838.410000 578.400000 ;
      RECT 1790.710000 577.620000 1812.610000 578.400000 ;
      RECT 1764.910000 577.620000 1786.810000 578.400000 ;
      RECT 1739.110000 577.620000 1761.010000 578.400000 ;
      RECT 1713.310000 577.620000 1735.210000 578.400000 ;
      RECT 1687.510000 577.620000 1709.410000 578.400000 ;
      RECT 1661.710000 577.620000 1683.610000 578.400000 ;
      RECT 1635.910000 577.620000 1657.810000 578.400000 ;
      RECT 1610.110000 577.620000 1632.010000 578.400000 ;
      RECT 1584.310000 577.620000 1606.210000 578.400000 ;
      RECT 1558.510000 577.620000 1580.410000 578.400000 ;
      RECT 1532.710000 577.620000 1554.610000 578.400000 ;
      RECT 1506.910000 577.620000 1528.810000 578.400000 ;
      RECT 500.710000 577.620000 522.610000 578.400000 ;
      RECT 474.910000 577.620000 496.810000 578.400000 ;
      RECT 449.110000 577.620000 471.010000 578.400000 ;
      RECT 423.310000 577.620000 445.210000 578.400000 ;
      RECT 397.510000 577.620000 419.410000 578.400000 ;
      RECT 371.710000 577.620000 393.610000 578.400000 ;
      RECT 345.910000 577.620000 367.810000 578.400000 ;
      RECT 320.110000 577.620000 342.010000 578.400000 ;
      RECT 294.310000 577.620000 316.210000 578.400000 ;
      RECT 268.510000 577.620000 290.410000 578.400000 ;
      RECT 242.710000 577.620000 264.610000 578.400000 ;
      RECT 216.910000 577.620000 238.810000 578.400000 ;
      RECT 191.110000 577.620000 213.010000 578.400000 ;
      RECT 165.310000 577.620000 187.210000 578.400000 ;
      RECT 139.510000 577.620000 161.410000 578.400000 ;
      RECT 113.710000 577.620000 135.610000 578.400000 ;
      RECT 1713.310000 519.220000 1713.610000 577.620000 ;
      RECT 1691.710000 519.220000 1709.410000 577.620000 ;
      RECT 1687.510000 519.220000 1687.810000 577.620000 ;
      RECT 1665.910000 519.220000 1683.610000 577.620000 ;
      RECT 1661.710000 519.220000 1662.010000 577.620000 ;
      RECT 1640.110000 519.220000 1657.810000 577.620000 ;
      RECT 1635.910000 519.220000 1636.210000 577.620000 ;
      RECT 1614.310000 519.220000 1632.010000 577.620000 ;
      RECT 1610.110000 519.220000 1610.410000 577.620000 ;
      RECT 1588.510000 519.220000 1606.210000 577.620000 ;
      RECT 1584.310000 519.220000 1584.610000 577.620000 ;
      RECT 1562.710000 519.220000 1580.410000 577.620000 ;
      RECT 1558.510000 519.220000 1558.810000 577.620000 ;
      RECT 1536.910000 519.220000 1554.610000 577.620000 ;
      RECT 1532.710000 519.220000 1533.010000 577.620000 ;
      RECT 1511.110000 519.220000 1528.810000 577.620000 ;
      RECT 1506.910000 519.220000 1507.210000 577.620000 ;
      RECT 1485.310000 519.220000 1503.010000 578.400000 ;
      RECT 1481.110000 519.220000 1481.410000 1498.400000 ;
      RECT 1459.510000 519.220000 1477.210000 1498.400000 ;
      RECT 1455.310000 519.220000 1455.610000 1498.400000 ;
      RECT 1433.710000 519.220000 1451.410000 1498.400000 ;
      RECT 1429.510000 519.220000 1429.810000 1498.400000 ;
      RECT 1407.910000 519.220000 1425.610000 1498.400000 ;
      RECT 1403.710000 519.220000 1404.010000 1498.400000 ;
      RECT 1382.110000 519.220000 1399.810000 1498.400000 ;
      RECT 1377.910000 519.220000 1378.210000 1498.400000 ;
      RECT 1356.310000 519.220000 1374.010000 1498.400000 ;
      RECT 1352.110000 519.220000 1352.410000 1498.400000 ;
      RECT 1330.510000 519.220000 1348.210000 1498.400000 ;
      RECT 1326.310000 519.220000 1326.610000 1498.400000 ;
      RECT 1304.710000 519.220000 1322.410000 1498.400000 ;
      RECT 1300.510000 519.220000 1300.810000 1498.400000 ;
      RECT 1278.910000 519.220000 1296.610000 1498.400000 ;
      RECT 1274.710000 519.220000 1275.010000 1498.400000 ;
      RECT 1253.110000 519.220000 1270.810000 1498.400000 ;
      RECT 1248.910000 519.220000 1249.210000 1498.400000 ;
      RECT 1227.310000 519.220000 1245.010000 1498.400000 ;
      RECT 1223.110000 519.220000 1223.410000 1498.400000 ;
      RECT 1201.510000 519.220000 1219.210000 1498.400000 ;
      RECT 1197.310000 519.220000 1197.610000 1498.400000 ;
      RECT 1175.710000 519.220000 1193.410000 1498.400000 ;
      RECT 1171.510000 519.220000 1171.810000 1498.400000 ;
      RECT 1149.910000 519.220000 1167.610000 1498.400000 ;
      RECT 1145.710000 519.220000 1146.010000 1498.400000 ;
      RECT 1124.110000 519.220000 1141.810000 1498.400000 ;
      RECT 1119.910000 519.220000 1120.210000 1498.400000 ;
      RECT 1098.310000 519.220000 1116.010000 1498.400000 ;
      RECT 1094.110000 519.220000 1094.410000 1498.400000 ;
      RECT 1072.510000 519.220000 1090.210000 1498.400000 ;
      RECT 1068.310000 519.220000 1068.610000 1498.400000 ;
      RECT 1046.710000 519.220000 1064.410000 1498.400000 ;
      RECT 1042.510000 519.220000 1042.810000 2000.080000 ;
      RECT 1020.910000 519.220000 1038.610000 2000.080000 ;
      RECT 939.310000 519.220000 939.610000 2000.080000 ;
      RECT 917.710000 519.220000 935.410000 1498.400000 ;
      RECT 913.510000 519.220000 913.810000 1498.400000 ;
      RECT 891.910000 519.220000 909.610000 1498.400000 ;
      RECT 887.710000 519.220000 888.010000 1498.400000 ;
      RECT 866.110000 519.220000 883.810000 1498.400000 ;
      RECT 861.910000 519.220000 862.210000 1498.400000 ;
      RECT 840.310000 519.220000 858.010000 1498.400000 ;
      RECT 836.110000 519.220000 836.410000 1498.400000 ;
      RECT 814.510000 519.220000 832.210000 1498.400000 ;
      RECT 810.310000 519.220000 810.610000 1498.400000 ;
      RECT 788.710000 519.220000 806.410000 1498.400000 ;
      RECT 784.510000 519.220000 784.810000 1498.400000 ;
      RECT 762.910000 519.220000 780.610000 1498.400000 ;
      RECT 758.710000 519.220000 759.010000 1498.400000 ;
      RECT 737.110000 519.220000 754.810000 1498.400000 ;
      RECT 732.910000 519.220000 733.210000 1498.400000 ;
      RECT 711.310000 519.220000 729.010000 1498.400000 ;
      RECT 707.110000 519.220000 707.410000 1498.400000 ;
      RECT 685.510000 519.220000 703.210000 1498.400000 ;
      RECT 681.310000 519.220000 681.610000 1498.400000 ;
      RECT 659.710000 519.220000 677.410000 1498.400000 ;
      RECT 655.510000 519.220000 655.810000 1498.400000 ;
      RECT 633.910000 519.220000 651.610000 1498.400000 ;
      RECT 629.710000 519.220000 630.010000 1498.400000 ;
      RECT 608.110000 519.220000 625.810000 1498.400000 ;
      RECT 603.910000 519.220000 604.210000 1498.400000 ;
      RECT 582.310000 519.220000 600.010000 1498.400000 ;
      RECT 578.110000 519.220000 578.410000 1498.400000 ;
      RECT 556.510000 519.220000 574.210000 1498.400000 ;
      RECT 552.310000 519.220000 552.610000 1498.400000 ;
      RECT 530.710000 519.220000 548.410000 1498.400000 ;
      RECT 526.510000 519.220000 526.810000 1498.400000 ;
      RECT 504.910000 519.220000 522.610000 577.620000 ;
      RECT 500.710000 519.220000 501.010000 577.620000 ;
      RECT 479.110000 519.220000 496.810000 577.620000 ;
      RECT 474.910000 519.220000 475.210000 577.620000 ;
      RECT 453.310000 519.220000 471.010000 577.620000 ;
      RECT 449.110000 519.220000 449.410000 577.620000 ;
      RECT 427.510000 519.220000 445.210000 577.620000 ;
      RECT 423.310000 519.220000 423.610000 577.620000 ;
      RECT 401.710000 519.220000 419.410000 577.620000 ;
      RECT 397.510000 519.220000 397.810000 577.620000 ;
      RECT 375.910000 519.220000 393.610000 577.620000 ;
      RECT 371.710000 519.220000 372.010000 577.620000 ;
      RECT 350.110000 519.220000 367.810000 577.620000 ;
      RECT 345.910000 519.220000 346.210000 577.620000 ;
      RECT 324.310000 519.220000 342.010000 577.620000 ;
      RECT 320.110000 519.220000 320.410000 577.620000 ;
      RECT 298.510000 519.220000 316.210000 577.620000 ;
      RECT 294.310000 519.220000 294.610000 577.620000 ;
      RECT 272.710000 519.220000 290.410000 577.620000 ;
      RECT 1691.710000 518.140000 1713.610000 519.220000 ;
      RECT 1665.910000 518.140000 1687.810000 519.220000 ;
      RECT 1640.110000 518.140000 1662.010000 519.220000 ;
      RECT 1614.310000 518.140000 1636.210000 519.220000 ;
      RECT 1588.510000 518.140000 1610.410000 519.220000 ;
      RECT 1562.710000 518.140000 1584.610000 519.220000 ;
      RECT 1536.910000 518.140000 1558.810000 519.220000 ;
      RECT 1511.110000 518.140000 1533.010000 519.220000 ;
      RECT 1485.310000 518.140000 1507.210000 519.220000 ;
      RECT 1459.510000 518.140000 1481.410000 519.220000 ;
      RECT 1433.710000 518.140000 1455.610000 519.220000 ;
      RECT 1407.910000 518.140000 1429.810000 519.220000 ;
      RECT 1382.110000 518.140000 1404.010000 519.220000 ;
      RECT 1356.310000 518.140000 1378.210000 519.220000 ;
      RECT 1330.510000 518.140000 1352.410000 519.220000 ;
      RECT 1304.710000 518.140000 1326.610000 519.220000 ;
      RECT 1278.910000 518.140000 1300.810000 519.220000 ;
      RECT 1253.110000 518.140000 1275.010000 519.220000 ;
      RECT 1227.310000 518.140000 1249.210000 519.220000 ;
      RECT 1201.510000 518.140000 1223.410000 519.220000 ;
      RECT 1175.710000 518.140000 1197.610000 519.220000 ;
      RECT 1149.910000 518.140000 1171.810000 519.220000 ;
      RECT 1124.110000 518.140000 1146.010000 519.220000 ;
      RECT 1098.310000 518.140000 1120.210000 519.220000 ;
      RECT 1072.510000 518.140000 1094.410000 519.220000 ;
      RECT 1046.710000 518.140000 1068.610000 519.220000 ;
      RECT 1020.910000 518.140000 1042.810000 519.220000 ;
      RECT 943.510000 518.140000 961.210000 2000.080000 ;
      RECT 917.710000 518.140000 939.610000 519.220000 ;
      RECT 891.910000 518.140000 913.810000 519.220000 ;
      RECT 866.110000 518.140000 888.010000 519.220000 ;
      RECT 840.310000 518.140000 862.210000 519.220000 ;
      RECT 814.510000 518.140000 836.410000 519.220000 ;
      RECT 788.710000 518.140000 810.610000 519.220000 ;
      RECT 762.910000 518.140000 784.810000 519.220000 ;
      RECT 737.110000 518.140000 759.010000 519.220000 ;
      RECT 711.310000 518.140000 733.210000 519.220000 ;
      RECT 685.510000 518.140000 707.410000 519.220000 ;
      RECT 659.710000 518.140000 681.610000 519.220000 ;
      RECT 633.910000 518.140000 655.810000 519.220000 ;
      RECT 608.110000 518.140000 630.010000 519.220000 ;
      RECT 582.310000 518.140000 604.210000 519.220000 ;
      RECT 556.510000 518.140000 578.410000 519.220000 ;
      RECT 530.710000 518.140000 552.610000 519.220000 ;
      RECT 504.910000 518.140000 526.810000 519.220000 ;
      RECT 479.110000 518.140000 501.010000 519.220000 ;
      RECT 453.310000 518.140000 475.210000 519.220000 ;
      RECT 427.510000 518.140000 449.410000 519.220000 ;
      RECT 401.710000 518.140000 423.610000 519.220000 ;
      RECT 375.910000 518.140000 397.810000 519.220000 ;
      RECT 350.110000 518.140000 372.010000 519.220000 ;
      RECT 324.310000 518.140000 346.210000 519.220000 ;
      RECT 298.510000 518.140000 320.410000 519.220000 ;
      RECT 272.710000 518.140000 294.610000 519.220000 ;
      RECT 268.510000 518.140000 268.810000 577.620000 ;
      RECT 1020.910000 98.400000 1713.610000 518.140000 ;
      RECT 268.510000 98.400000 961.210000 518.140000 ;
      RECT 1997.110000 0.000000 2000.080000 2000.080000 ;
      RECT 1975.510000 0.000000 1993.210000 2000.080000 ;
      RECT 1971.310000 0.000000 1971.610000 2000.080000 ;
      RECT 1949.710000 0.000000 1967.410000 2000.080000 ;
      RECT 1945.510000 0.000000 1945.810000 2000.080000 ;
      RECT 1923.910000 0.000000 1941.610000 2000.080000 ;
      RECT 1919.710000 0.000000 1920.010000 578.400000 ;
      RECT 1898.110000 0.000000 1915.810000 577.620000 ;
      RECT 1893.910000 0.000000 1894.210000 577.620000 ;
      RECT 1872.310000 0.000000 1890.010000 577.620000 ;
      RECT 1868.110000 0.000000 1868.410000 577.620000 ;
      RECT 1846.510000 0.000000 1864.210000 577.620000 ;
      RECT 1842.310000 0.000000 1842.610000 577.620000 ;
      RECT 1820.710000 0.000000 1838.410000 577.620000 ;
      RECT 1816.510000 0.000000 1816.810000 577.620000 ;
      RECT 1794.910000 0.000000 1812.610000 577.620000 ;
      RECT 1790.710000 0.000000 1791.010000 577.620000 ;
      RECT 1769.110000 0.000000 1786.810000 577.620000 ;
      RECT 1764.910000 0.000000 1765.210000 577.620000 ;
      RECT 1743.310000 0.000000 1761.010000 577.620000 ;
      RECT 1739.110000 0.000000 1739.410000 577.620000 ;
      RECT 1717.510000 0.000000 1735.210000 577.620000 ;
      RECT 1713.310000 0.000000 1713.610000 98.400000 ;
      RECT 1691.710000 0.000000 1709.410000 98.400000 ;
      RECT 1687.510000 0.000000 1687.810000 98.400000 ;
      RECT 1665.910000 0.000000 1683.610000 98.400000 ;
      RECT 1661.710000 0.000000 1662.010000 98.400000 ;
      RECT 1640.110000 0.000000 1657.810000 98.400000 ;
      RECT 1635.910000 0.000000 1636.210000 98.400000 ;
      RECT 1614.310000 0.000000 1632.010000 98.400000 ;
      RECT 1610.110000 0.000000 1610.410000 98.400000 ;
      RECT 1588.510000 0.000000 1606.210000 98.400000 ;
      RECT 1584.310000 0.000000 1584.610000 98.400000 ;
      RECT 1562.710000 0.000000 1580.410000 98.400000 ;
      RECT 1558.510000 0.000000 1558.810000 98.400000 ;
      RECT 1536.910000 0.000000 1554.610000 98.400000 ;
      RECT 1532.710000 0.000000 1533.010000 98.400000 ;
      RECT 1511.110000 0.000000 1528.810000 98.400000 ;
      RECT 1506.910000 0.000000 1507.210000 98.400000 ;
      RECT 1485.310000 0.000000 1503.010000 98.400000 ;
      RECT 1481.110000 0.000000 1481.410000 98.400000 ;
      RECT 1459.510000 0.000000 1477.210000 98.400000 ;
      RECT 1455.310000 0.000000 1455.610000 98.400000 ;
      RECT 1433.710000 0.000000 1451.410000 98.400000 ;
      RECT 1429.510000 0.000000 1429.810000 98.400000 ;
      RECT 1407.910000 0.000000 1425.610000 98.400000 ;
      RECT 1403.710000 0.000000 1404.010000 98.400000 ;
      RECT 1382.110000 0.000000 1399.810000 98.400000 ;
      RECT 1377.910000 0.000000 1378.210000 98.400000 ;
      RECT 1356.310000 0.000000 1374.010000 98.400000 ;
      RECT 1352.110000 0.000000 1352.410000 98.400000 ;
      RECT 1330.510000 0.000000 1348.210000 98.400000 ;
      RECT 1326.310000 0.000000 1326.610000 98.400000 ;
      RECT 1304.710000 0.000000 1322.410000 98.400000 ;
      RECT 1300.510000 0.000000 1300.810000 98.400000 ;
      RECT 1278.910000 0.000000 1296.610000 98.400000 ;
      RECT 1274.710000 0.000000 1275.010000 98.400000 ;
      RECT 1253.110000 0.000000 1270.810000 98.400000 ;
      RECT 1248.910000 0.000000 1249.210000 98.400000 ;
      RECT 1227.310000 0.000000 1245.010000 98.400000 ;
      RECT 1223.110000 0.000000 1223.410000 98.400000 ;
      RECT 1201.510000 0.000000 1219.210000 98.400000 ;
      RECT 1197.310000 0.000000 1197.610000 98.400000 ;
      RECT 1175.710000 0.000000 1193.410000 98.400000 ;
      RECT 1171.510000 0.000000 1171.810000 98.400000 ;
      RECT 1149.910000 0.000000 1167.610000 98.400000 ;
      RECT 1145.710000 0.000000 1146.010000 98.400000 ;
      RECT 1124.110000 0.000000 1141.810000 98.400000 ;
      RECT 1119.910000 0.000000 1120.210000 98.400000 ;
      RECT 1098.310000 0.000000 1116.010000 98.400000 ;
      RECT 1094.110000 0.000000 1094.410000 98.400000 ;
      RECT 1072.510000 0.000000 1090.210000 98.400000 ;
      RECT 1068.310000 0.000000 1068.610000 98.400000 ;
      RECT 1046.710000 0.000000 1064.410000 98.400000 ;
      RECT 1042.510000 0.000000 1042.810000 98.400000 ;
      RECT 1020.910000 0.000000 1038.610000 98.400000 ;
      RECT 1016.710000 0.000000 1017.010000 2000.080000 ;
      RECT 995.110000 0.000000 1012.810000 2000.080000 ;
      RECT 990.910000 0.000000 991.210000 2000.080000 ;
      RECT 969.310000 0.000000 987.010000 2000.080000 ;
      RECT 965.110000 0.000000 965.410000 2000.080000 ;
      RECT 943.510000 0.000000 961.210000 98.400000 ;
      RECT 939.310000 0.000000 939.610000 98.400000 ;
      RECT 917.710000 0.000000 935.410000 98.400000 ;
      RECT 913.510000 0.000000 913.810000 98.400000 ;
      RECT 891.910000 0.000000 909.610000 98.400000 ;
      RECT 887.710000 0.000000 888.010000 98.400000 ;
      RECT 866.110000 0.000000 883.810000 98.400000 ;
      RECT 861.910000 0.000000 862.210000 98.400000 ;
      RECT 840.310000 0.000000 858.010000 98.400000 ;
      RECT 836.110000 0.000000 836.410000 98.400000 ;
      RECT 814.510000 0.000000 832.210000 98.400000 ;
      RECT 810.310000 0.000000 810.610000 98.400000 ;
      RECT 788.710000 0.000000 806.410000 98.400000 ;
      RECT 784.510000 0.000000 784.810000 98.400000 ;
      RECT 762.910000 0.000000 780.610000 98.400000 ;
      RECT 758.710000 0.000000 759.010000 98.400000 ;
      RECT 737.110000 0.000000 754.810000 98.400000 ;
      RECT 732.910000 0.000000 733.210000 98.400000 ;
      RECT 711.310000 0.000000 729.010000 98.400000 ;
      RECT 707.110000 0.000000 707.410000 98.400000 ;
      RECT 685.510000 0.000000 703.210000 98.400000 ;
      RECT 681.310000 0.000000 681.610000 98.400000 ;
      RECT 659.710000 0.000000 677.410000 98.400000 ;
      RECT 655.510000 0.000000 655.810000 98.400000 ;
      RECT 633.910000 0.000000 651.610000 98.400000 ;
      RECT 629.710000 0.000000 630.010000 98.400000 ;
      RECT 608.110000 0.000000 625.810000 98.400000 ;
      RECT 603.910000 0.000000 604.210000 98.400000 ;
      RECT 582.310000 0.000000 600.010000 98.400000 ;
      RECT 578.110000 0.000000 578.410000 98.400000 ;
      RECT 556.510000 0.000000 574.210000 98.400000 ;
      RECT 552.310000 0.000000 552.610000 98.400000 ;
      RECT 530.710000 0.000000 548.410000 98.400000 ;
      RECT 526.510000 0.000000 526.810000 98.400000 ;
      RECT 504.910000 0.000000 522.610000 98.400000 ;
      RECT 500.710000 0.000000 501.010000 98.400000 ;
      RECT 479.110000 0.000000 496.810000 98.400000 ;
      RECT 474.910000 0.000000 475.210000 98.400000 ;
      RECT 453.310000 0.000000 471.010000 98.400000 ;
      RECT 449.110000 0.000000 449.410000 98.400000 ;
      RECT 427.510000 0.000000 445.210000 98.400000 ;
      RECT 423.310000 0.000000 423.610000 98.400000 ;
      RECT 401.710000 0.000000 419.410000 98.400000 ;
      RECT 397.510000 0.000000 397.810000 98.400000 ;
      RECT 375.910000 0.000000 393.610000 98.400000 ;
      RECT 371.710000 0.000000 372.010000 98.400000 ;
      RECT 350.110000 0.000000 367.810000 98.400000 ;
      RECT 345.910000 0.000000 346.210000 98.400000 ;
      RECT 324.310000 0.000000 342.010000 98.400000 ;
      RECT 320.110000 0.000000 320.410000 98.400000 ;
      RECT 298.510000 0.000000 316.210000 98.400000 ;
      RECT 294.310000 0.000000 294.610000 98.400000 ;
      RECT 272.710000 0.000000 290.410000 98.400000 ;
      RECT 268.510000 0.000000 268.810000 98.400000 ;
      RECT 246.910000 0.000000 264.610000 577.620000 ;
      RECT 242.710000 0.000000 243.010000 577.620000 ;
      RECT 221.110000 0.000000 238.810000 577.620000 ;
      RECT 216.910000 0.000000 217.210000 577.620000 ;
      RECT 195.310000 0.000000 213.010000 577.620000 ;
      RECT 191.110000 0.000000 191.410000 577.620000 ;
      RECT 169.510000 0.000000 187.210000 577.620000 ;
      RECT 165.310000 0.000000 165.610000 577.620000 ;
      RECT 143.710000 0.000000 161.410000 577.620000 ;
      RECT 139.510000 0.000000 139.810000 577.620000 ;
      RECT 117.910000 0.000000 135.610000 577.620000 ;
      RECT 113.710000 0.000000 114.010000 577.620000 ;
      RECT 92.110000 0.000000 109.810000 578.400000 ;
      RECT 87.910000 0.000000 88.210000 2000.080000 ;
      RECT 66.310000 0.000000 84.010000 2000.080000 ;
      RECT 62.110000 0.000000 62.410000 2000.080000 ;
      RECT 40.510000 0.000000 58.210000 2000.080000 ;
      RECT 36.310000 0.000000 36.610000 2000.080000 ;
      RECT 14.710000 0.000000 32.410000 2000.080000 ;
      RECT 10.510000 0.000000 10.810000 2000.080000 ;
      RECT 0.000000 0.000000 6.610000 2000.080000 ;
  END
END SoC_Tile

END LIBRARY
